(* Logix 5000 project; controller ANG1E_AOI_CompactLogix_RSLogix_V28 vendor 1 type 14 code 108 rev 28.11; software revision 28.00; part 2 of 5 *)
(* tags used below, declared in another part *)
   Least_Significant_Word : INT;

ADD_ON_INSTRUCTION AMCI_ANG1E_Hold   (* revision 1.1, vendor AMCI *)
// Revision note:
// Version 1.1 added the slot_axis number and the input parameters can now be tags or discrete values.
VAR_INPUT
   slot_axis_number : INT; {required}
END_VAR
VAR_IN_OUT
   AMCI_ANG1E_output_data : INT[10]; {required}
END_VAR
VAR
   command_data_block : INT[10];
        [5]   // Lower Programmed Speed
        [0]   // Command Bits MSW
        [1]   // Command Bits LSW
        [3]   // Lower Target Position
        [2]   // Upper Target Position
        [4]   // Upper Programmed Speed
   index : INT;
END_VAR

ROUTINE Logic   (* ladder *)
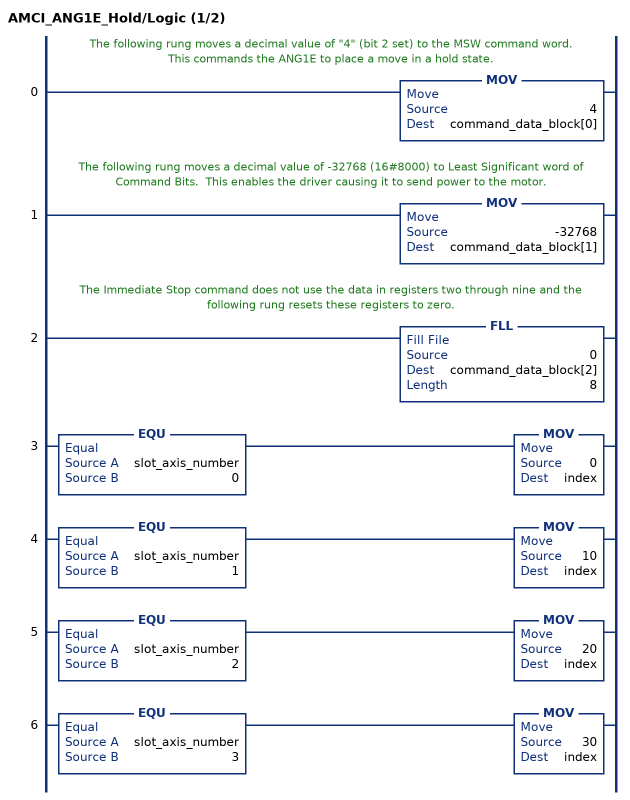
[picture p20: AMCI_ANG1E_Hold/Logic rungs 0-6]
   // The following rung moves a decimal value of "4" (bit 2 set) to the MSW command word.  This commands the ANG1E to place a move in a hold state.
   0: MOV(4,command_data_block[0]);
   // The following rung moves a decimal value of -32768 (16#8000) to Least Significant word of Command Bits.  This enables the driver causing it to send power to the motor.
   1: MOV(-32768,command_data_block[1]);
   // The Immediate Stop command does not use the data in registers two through nine and the following rung resets these registers to zero.
   2: FLL(0,command_data_block[2],8);
   3: EQU(slot_axis_number,0)MOV(0,index);
   4: EQU(slot_axis_number,1)MOV(10,index);
   5: EQU(slot_axis_number,2)MOV(20,index);
   6: EQU(slot_axis_number,3)MOV(30,index);
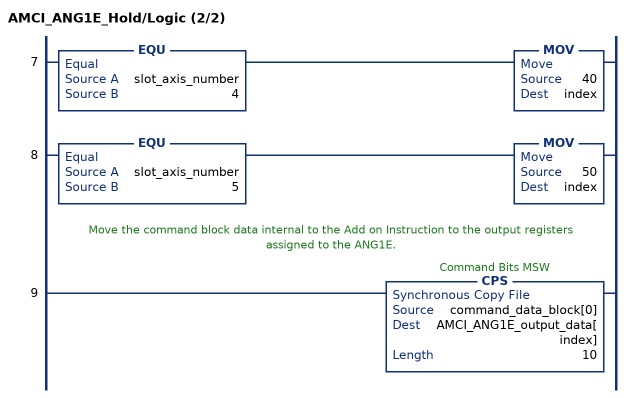
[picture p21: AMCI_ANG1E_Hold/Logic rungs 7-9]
   7: EQU(slot_axis_number,4)MOV(40,index);
   8: EQU(slot_axis_number,5)MOV(50,index);
   // Move the command block data internal to the Add on Instruction to the output registers assigned to the ANG1E.
   9: CPS(command_data_block[0],AMCI_ANG1E_output_data[index],10);
END_ROUTINE
END_ADD_ON_INSTRUCTION

ADD_ON_INSTRUCTION AMCI_ANG1E_Home_CCW   (* revision 5.0, vendor AMCI, ExecuteEnableInFalse *)
// Revision note:
// Version 5.0 added the (hidden) ability to program the motor current and unlatched the error bit if the rung goes false.
VAR_INPUT
   Axis_Status_Bits : INT; {required}
   slot_axis_number : INT; {required}
   Type_0_for_standard_1_for_indexed : BOOL;
   Programmed_Speed : DINT; {required}
   Acceleration : INT; {required}
   Deceleration : INT; {required}
   motor_current : INT;
   jerk : INT;
END_VAR
VAR_IN_OUT
   AMCI_ANG1E_output_data : INT[10]; {required}
END_VAR
VAR_OUTPUT
   EN : BOOL; {access Read Only, visible}
   ER : BOOL; {access Read Only, visible}
END_VAR
VAR
   Upper_Result_X_1000 : DINT;
   command_data_block : INT[10];
        [1]   // Command Bits LSW
        [3]   // Lower Target Position
        [5]   // Lower Programmed Speed
        [0]   // Command Bits MSW
        [2]   // Upper Target Position
        [4]   // Upper Programmed Speed
   index : INT;
END_VAR

ROUTINE EnableInFalse   (* ladder *)
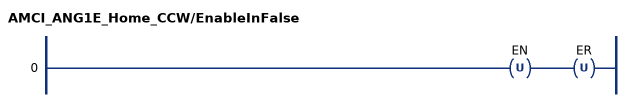
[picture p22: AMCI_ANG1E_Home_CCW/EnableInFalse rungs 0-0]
   0: OTU(EN)OTU(ER);
END_ROUTINE

ROUTINE Logic   (* ladder *)
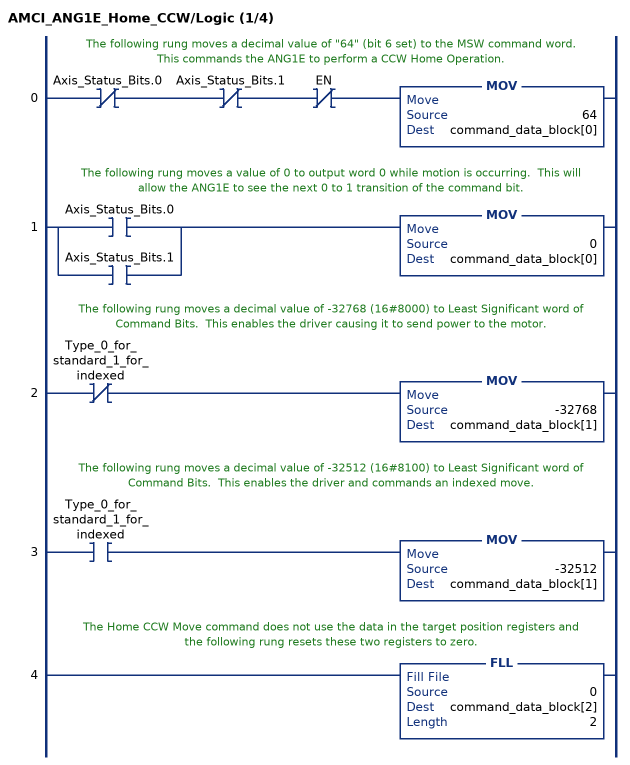
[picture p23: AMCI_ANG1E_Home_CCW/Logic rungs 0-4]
   // The following rung moves a decimal value of "64" (bit 6 set) to the MSW command word.  This commands the ANG1E to perform a CCW Home Operation.
   0: XIO(Axis_Status_Bits.0)XIO(Axis_Status_Bits.1)XIO(EN)MOV(64,command_data_block[0]);
   // The following rung moves a value of 0 to output word 0 while motion is occurring.  This will allow the ANG1E to see the next 0 to 1 transition of the command bit.
   1: [XIC(Axis_Status_Bits.0) ,XIC(Axis_Status_Bits.1) ]MOV(0,command_data_block[0]);
   // The following rung moves a decimal value of -32768 (16#8000) to Least Significant word of Command Bits.  This enables the driver causing it to send power to the motor.
   2: XIO(Type_0_for_standard_1_for_indexed)MOV(-32768,command_data_block[1]);
   // The following rung moves a decimal value of -32512 (16#8100) to Least Significant word of Command Bits.  This enables the driver and commands an indexed move.
   3: XIC(Type_0_for_standard_1_for_indexed)MOV(-32512,command_data_block[1]);
   // The Home CCW Move command does not use the data in the target position registers and the following rung resets these two registers to zero.
   4: FLL(0,command_data_block[2],2);
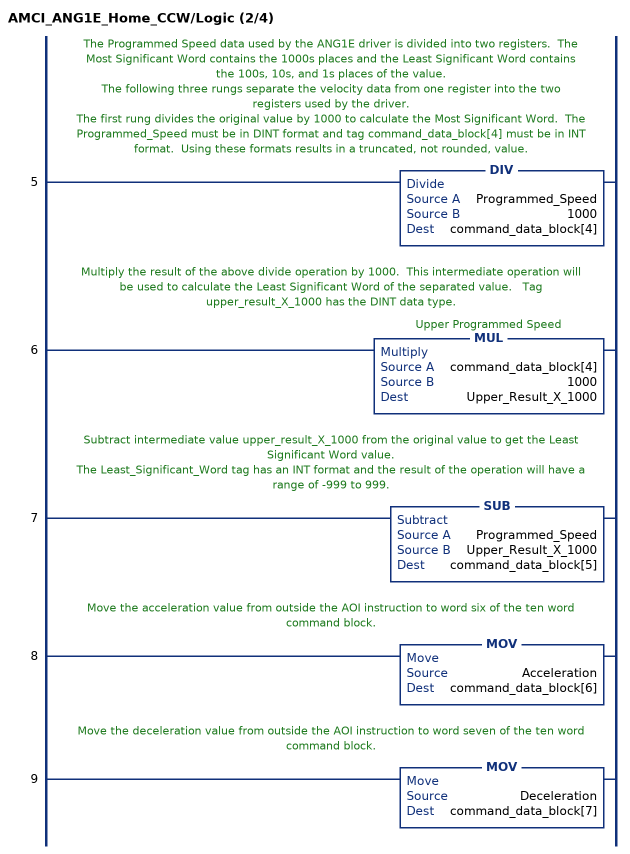
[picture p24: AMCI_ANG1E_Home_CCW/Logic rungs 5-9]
   // The Programmed Speed data used by the ANG1E driver is divided into two registers.  The Most Significant Word contains the 1000s places and the Least Significant Word contains the 100s, 10s, and 1s places of the value.
   // The following three rungs separate the velocity data from one register into the two registers used by the driver.
   // The first rung divides the original value by 1000 to calculate the Most Significant Word.  The Programmed_Speed must be in DINT format and tag command_data_block[4] must be in INT format.  Using these formats results in a truncated, not rounded, value.
   5: DIV(Programmed_Speed,1000,command_data_block[4]);
   // Multiply the result of the above divide operation by 1000.  This intermediate operation will be used to calculate the Least Significant Word of the separated value.   Tag upper_result_X_1000 has the DINT data type.
   6: MUL(command_data_block[4],1000,Upper_Result_X_1000);
   // Subtract intermediate value upper_result_X_1000 from the original value to get the Least Significant Word value.
   // The Least_Significant_Word tag has an INT format and the result of the operation will have a range of -999 to 999.
   7: SUB(Programmed_Speed,Upper_Result_X_1000,command_data_block[5]);
   // Move the acceleration value from outside the AOI instruction to word six of the ten word command block.
   8: MOV(Acceleration,command_data_block[6]);
   // Move the deceleration value from outside the AOI instruction to word seven of the ten word command block.
   9: MOV(Deceleration,command_data_block[7]);
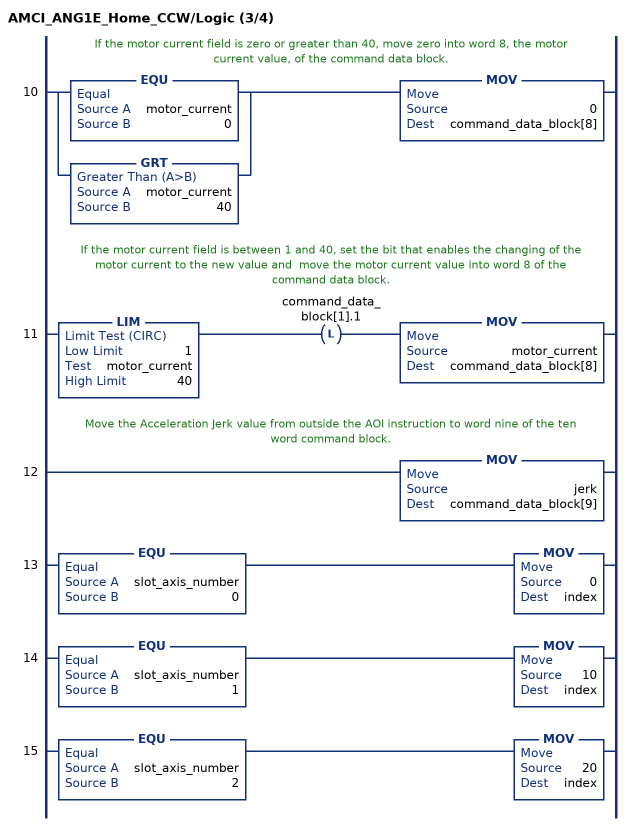
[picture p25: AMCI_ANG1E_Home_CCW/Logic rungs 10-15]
   // If the motor current field is zero or greater than 40, move zero into word 8, the motor current value, of the command data block.
   10: [EQU(motor_current,0) ,GRT(motor_current,40) ]MOV(0,command_data_block[8]);
   // If the motor current field is between 1 and 40, set the bit that enables the changing of the motor current to the new value and  move the motor current value into word 8 of the command data block.
   11: LIM(1,motor_current,40)OTL(command_data_block[1].1)MOV(motor_current,command_data_block[8]);
   // Move the Acceleration Jerk value from outside the AOI instruction to word nine of the ten word command block.
   12: MOV(jerk,command_data_block[9]);
   13: EQU(slot_axis_number,0)MOV(0,index);
   14: EQU(slot_axis_number,1)MOV(10,index);
   15: EQU(slot_axis_number,2)MOV(20,index);
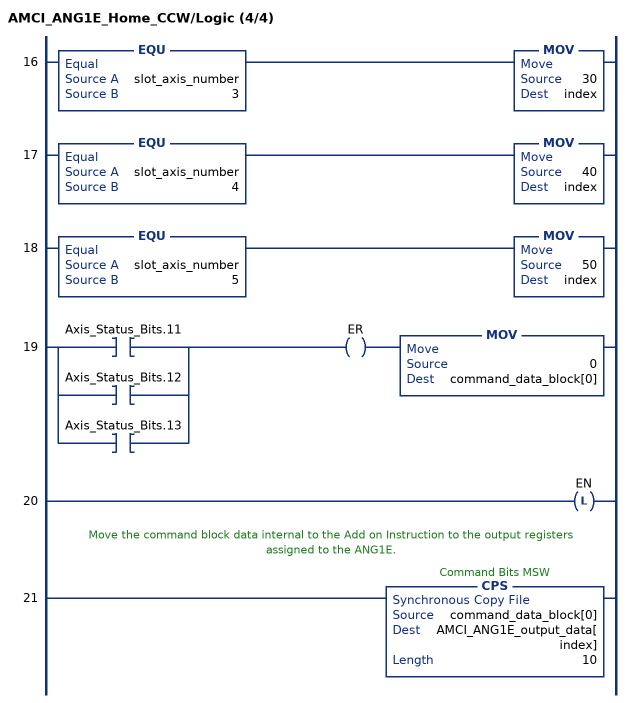
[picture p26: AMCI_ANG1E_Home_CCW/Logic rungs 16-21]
   16: EQU(slot_axis_number,3)MOV(30,index);
   17: EQU(slot_axis_number,4)MOV(40,index);
   18: EQU(slot_axis_number,5)MOV(50,index);
   19: [XIC(Axis_Status_Bits.11) ,XIC(Axis_Status_Bits.12) ,XIC(Axis_Status_Bits.13) ]OTE(ER)MOV(0,command_data_block[0]);
   20: OTL(EN);
   // Move the command block data internal to the Add on Instruction to the output registers assigned to the ANG1E.
   21: CPS(command_data_block[0],AMCI_ANG1E_output_data[index],10);
END_ROUTINE
END_ADD_ON_INSTRUCTION

ADD_ON_INSTRUCTION AMCI_ANG1E_Home_CW   (* revision 5.0, vendor AMCI, ExecuteEnableInFalse *)
// Revision note:
// Version 5.0 added the (hidden) ability to program the motor current and unlatched the error bit if the rung goes false.
VAR_INPUT
   Axis_Status_Bits : INT; {required}
   slot_axis_number : INT; {required}
   type_0_for_standard_1_for_indexed : BOOL;
   Programmed_Speed : DINT; {required}
   Acceleration : INT; {required}
   Deceleration : INT; {required}
   motor_current : INT;
   jerk : INT;
END_VAR
VAR_IN_OUT
   AMCI_ANG1E_output_data : INT[10]; {required}
END_VAR
VAR_OUTPUT
   EN : BOOL; {access Read Only, visible}
   ER : BOOL; {access Read Only, visible}
END_VAR
VAR
   Upper_Result_X_1000 : DINT;
   command_data_block : INT[10];
        [1]   // Command Bits LSW
        [3]   // Lower Target Position
        [5]   // Lower Programmed Speed
        [0]   // Command Bits MSW
        [2]   // Upper Target Position
        [4]   // Upper Programmed Speed
   index : INT;
END_VAR

ROUTINE EnableInFalse   (* ladder *)
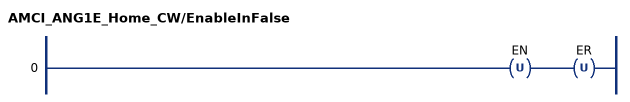
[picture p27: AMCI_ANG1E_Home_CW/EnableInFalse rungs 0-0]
   0: OTU(EN)OTU(ER);
END_ROUTINE

ROUTINE Logic   (* ladder *)
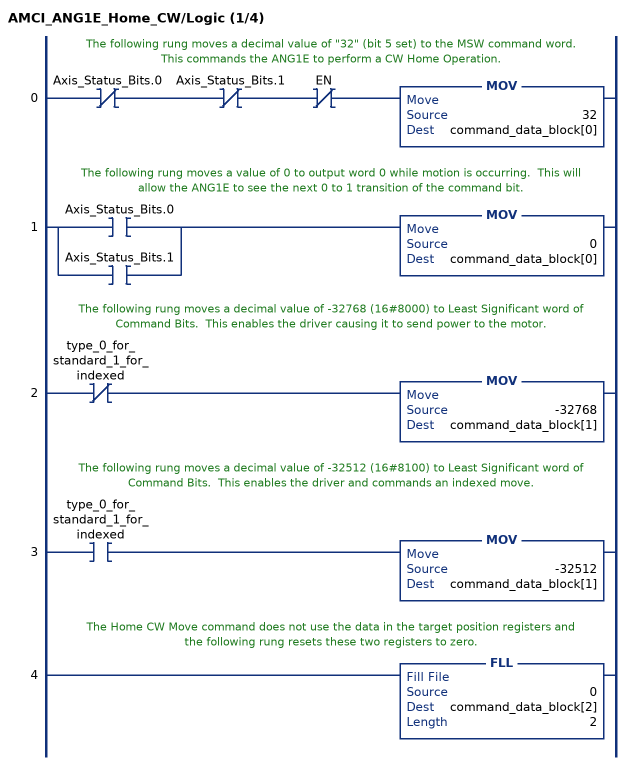
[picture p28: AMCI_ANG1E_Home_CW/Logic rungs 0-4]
   // The following rung moves a decimal value of "32" (bit 5 set) to the MSW command word.  This commands the ANG1E to perform a CW Home Operation.
   0: XIO(Axis_Status_Bits.0)XIO(Axis_Status_Bits.1)XIO(EN)MOV(32,command_data_block[0]);
   // The following rung moves a value of 0 to output word 0 while motion is occurring.  This will allow the ANG1E to see the next 0 to 1 transition of the command bit.
   1: [XIC(Axis_Status_Bits.0) ,XIC(Axis_Status_Bits.1) ]MOV(0,command_data_block[0]);
   // The following rung moves a decimal value of -32768 (16#8000) to Least Significant word of Command Bits.  This enables the driver causing it to send power to the motor.
   2: XIO(type_0_for_standard_1_for_indexed)MOV(-32768,command_data_block[1]);
   // The following rung moves a decimal value of -32512 (16#8100) to Least Significant word of Command Bits.  This enables the driver and commands an indexed move.
   3: XIC(type_0_for_standard_1_for_indexed)MOV(-32512,command_data_block[1]);
   // The Home CW Move command does not use the data in the target position registers and the following rung resets these two registers to zero.
   4: FLL(0,command_data_block[2],2);
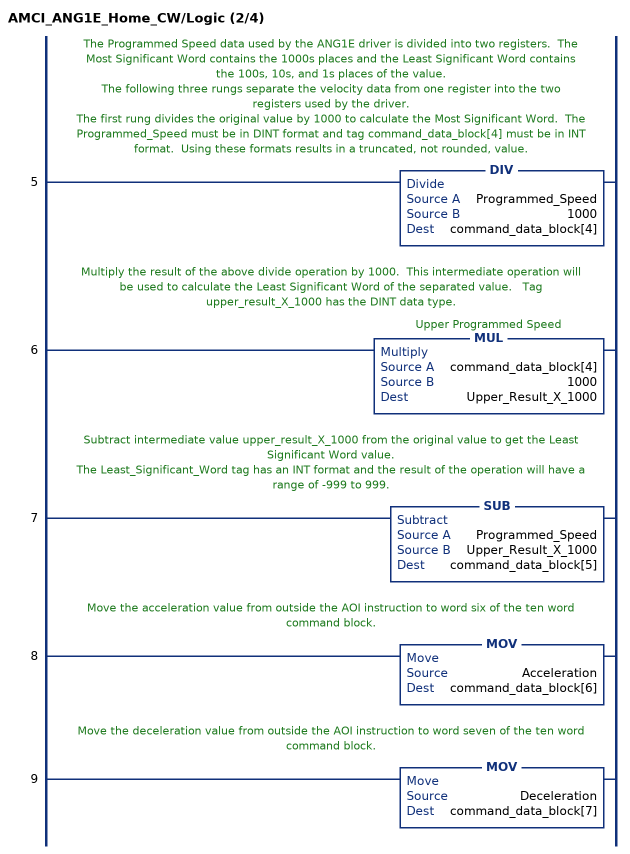
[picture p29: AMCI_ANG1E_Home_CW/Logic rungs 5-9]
   // The Programmed Speed data used by the ANG1E driver is divided into two registers.  The Most Significant Word contains the 1000s places and the Least Significant Word contains the 100s, 10s, and 1s places of the value.
   // The following three rungs separate the velocity data from one register into the two registers used by the driver.
   // The first rung divides the original value by 1000 to calculate the Most Significant Word.  The Programmed_Speed must be in DINT format and tag command_data_block[4] must be in INT format.  Using these formats results in a truncated, not rounded, value.
   5: DIV(Programmed_Speed,1000,command_data_block[4]);
   // Multiply the result of the above divide operation by 1000.  This intermediate operation will be used to calculate the Least Significant Word of the separated value.   Tag upper_result_X_1000 has the DINT data type.
   6: MUL(command_data_block[4],1000,Upper_Result_X_1000);
   // Subtract intermediate value upper_result_X_1000 from the original value to get the Least Significant Word value.
   // The Least_Significant_Word tag has an INT format and the result of the operation will have a range of -999 to 999.
   7: SUB(Programmed_Speed,Upper_Result_X_1000,command_data_block[5]);
   // Move the acceleration value from outside the AOI instruction to word six of the ten word command block.
   8: MOV(Acceleration,command_data_block[6]);
   // Move the deceleration value from outside the AOI instruction to word seven of the ten word command block.
   9: MOV(Deceleration,command_data_block[7]);
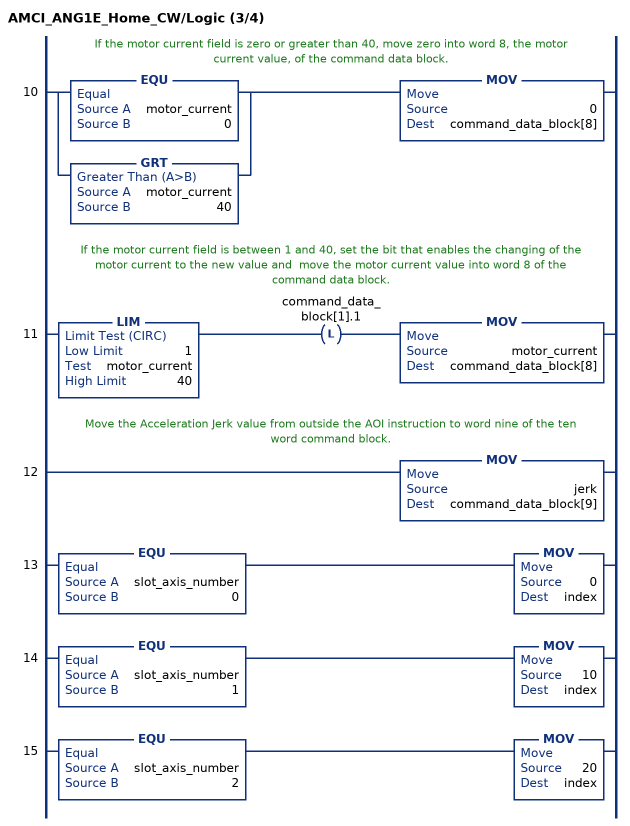
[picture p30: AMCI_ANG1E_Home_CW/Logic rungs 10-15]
   // If the motor current field is zero or greater than 40, move zero into word 8, the motor current value, of the command data block.
   10: [EQU(motor_current,0) ,GRT(motor_current,40) ]MOV(0,command_data_block[8]);
   // If the motor current field is between 1 and 40, set the bit that enables the changing of the motor current to the new value and  move the motor current value into word 8 of the command data block.
   11: LIM(1,motor_current,40)OTL(command_data_block[1].1)MOV(motor_current,command_data_block[8]);
   // Move the Acceleration Jerk value from outside the AOI instruction to word nine of the ten word command block.
   12: MOV(jerk,command_data_block[9]);
   13: EQU(slot_axis_number,0)MOV(0,index);
   14: EQU(slot_axis_number,1)MOV(10,index);
   15: EQU(slot_axis_number,2)MOV(20,index);
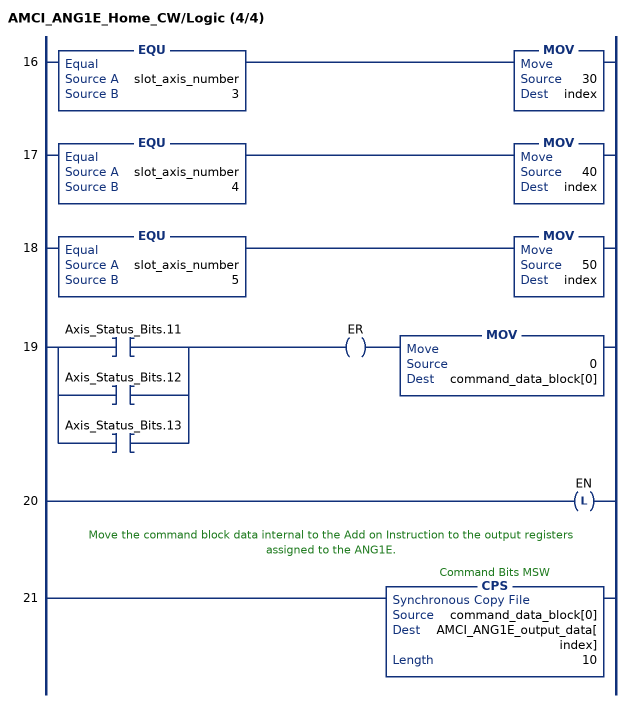
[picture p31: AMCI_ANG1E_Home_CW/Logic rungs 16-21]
   16: EQU(slot_axis_number,3)MOV(30,index);
   17: EQU(slot_axis_number,4)MOV(40,index);
   18: EQU(slot_axis_number,5)MOV(50,index);
   19: [XIC(Axis_Status_Bits.11) ,XIC(Axis_Status_Bits.12) ,XIC(Axis_Status_Bits.13) ]OTE(ER)MOV(0,command_data_block[0]);
   20: OTL(EN);
   // Move the command block data internal to the Add on Instruction to the output registers assigned to the ANG1E.
   21: CPS(command_data_block[0],AMCI_ANG1E_output_data[index],10);
END_ROUTINE
END_ADD_ON_INSTRUCTION

ADD_ON_INSTRUCTION AMCI_ANG1E_Immediate_Stop   (* revision 1.1, vendor AMCI *)
// Revision note:
// Version 1.1 added the slot_axis number and the input parameters can now be tags or discrete values.
VAR_INPUT
   slot_axis_number : INT; {required}
END_VAR
VAR_IN_OUT
   AMCI_ANG1E_output_data : INT[10]; {required}
END_VAR
VAR
   command_data_block : INT[10];
        [1]   // Command Bits LSW
        [3]   // Lower Target Position
        [5]   // Lower Programmed Speed
        [0]   // Command Bits MSW
        [2]   // Upper Target Position
        [4]   // Upper Programmed Speed
   index : INT;
END_VAR

ROUTINE Logic   (* ladder *)
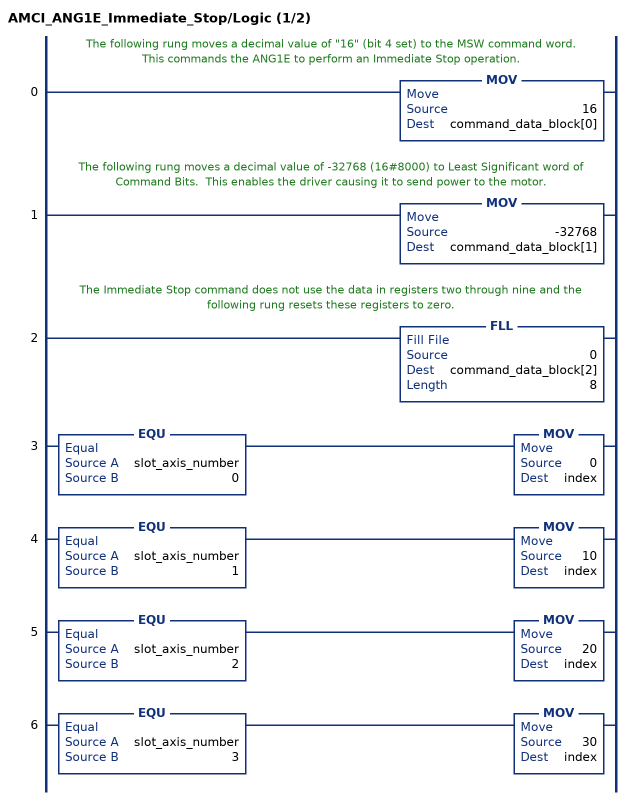
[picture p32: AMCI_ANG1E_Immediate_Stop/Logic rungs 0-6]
   // The following rung moves a decimal value of "16" (bit 4 set) to the MSW command word.  This commands the ANG1E to perform an Immediate Stop operation.
   0: MOV(16,command_data_block[0]);
   // The following rung moves a decimal value of -32768 (16#8000) to Least Significant word of Command Bits.  This enables the driver causing it to send power to the motor.
   1: MOV(-32768,command_data_block[1]);
   // The Immediate Stop command does not use the data in registers two through nine and the following rung resets these registers to zero.
   2: FLL(0,command_data_block[2],8);
   3: EQU(slot_axis_number,0)MOV(0,index);
   4: EQU(slot_axis_number,1)MOV(10,index);
   5: EQU(slot_axis_number,2)MOV(20,index);
   6: EQU(slot_axis_number,3)MOV(30,index);
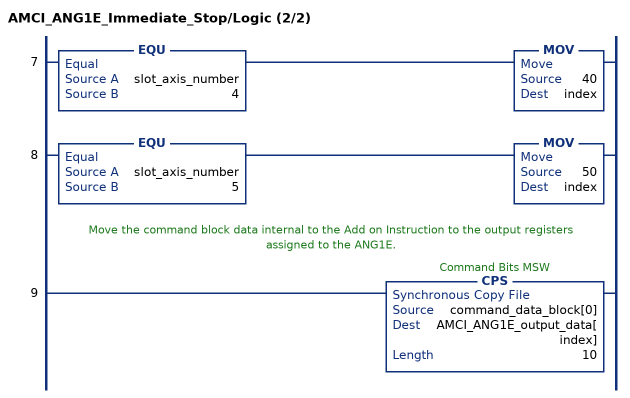
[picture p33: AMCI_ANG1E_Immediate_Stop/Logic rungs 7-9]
   7: EQU(slot_axis_number,4)MOV(40,index);
   8: EQU(slot_axis_number,5)MOV(50,index);
   // Move the command block data internal to the Add on Instruction to the output registers assigned to the ANG1E.
   9: CPS(command_data_block[0],AMCI_ANG1E_output_data[index],10);
END_ROUTINE
END_ADD_ON_INSTRUCTION

ADD_ON_INSTRUCTION AMCI_ANG1E_Jog_CCW   (* revision 5.0, vendor AMCI, ExecuteEnableInFalse *)
// Revision note:
// Version 5.0 added the (hidden) ability to program the motor current and unlatched the error bit if the rung goes false.
VAR_INPUT
   Axis_Status_Bits : DINT; {required}
   slot_axis_number : INT; {required}
   Programmed_Speed : DINT; {required}
   Acceleration : INT; {required}
   Deceleration : INT; {required}
   motor_current : INT;
   jerk : INT;
END_VAR
VAR_IN_OUT
   AMCI_ANG1E_output_data : INT[10]; {required}
END_VAR
VAR_OUTPUT
   EN : BOOL; {access Read Only, visible}
   Jog_CCW_Occurring : BOOL; {access Read Only, visible}
   ER : BOOL; {access Read Only, visible}
END_VAR
VAR
   Upper_Result_X_1000 : DINT;
   command_data_block : INT[10];
        [1]   // Command Bits LSW
        [3]   // Lower Target Position
        [5]   // Lower Programmed Speed
        [0]   // Command Bits MSW
        [2]   // Upper Target Position
        [4]   // Upper Programmed Speed
   index : INT;
END_VAR

ROUTINE EnableInFalse   (* ladder *)
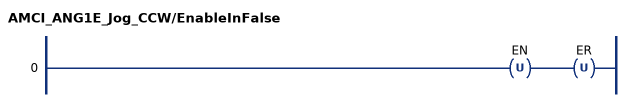
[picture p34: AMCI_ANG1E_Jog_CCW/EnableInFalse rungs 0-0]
   0: OTU(EN)OTU(ER);
END_ROUTINE

ROUTINE Logic   (* ladder *)
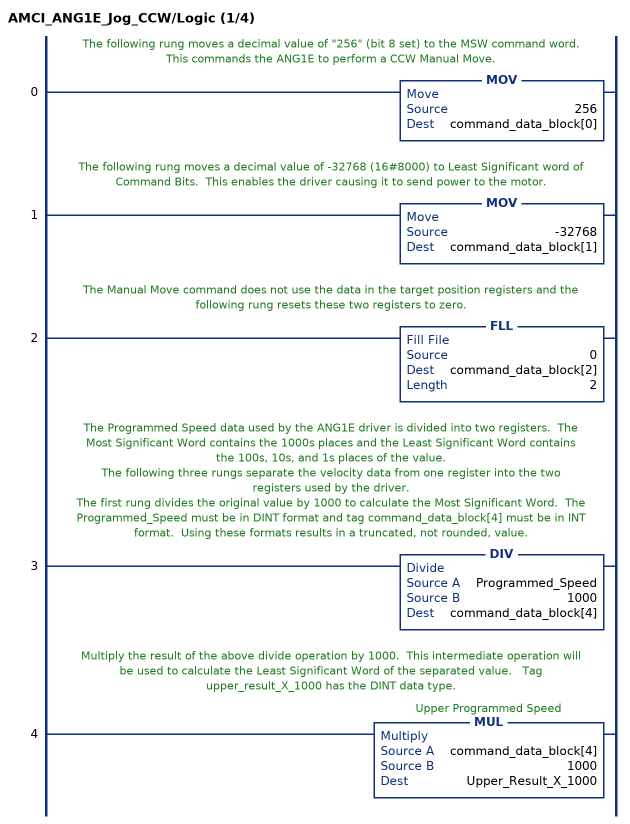
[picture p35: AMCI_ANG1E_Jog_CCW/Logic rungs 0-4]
   // The following rung moves a decimal value of "256" (bit 8 set) to the MSW command word.  This commands the ANG1E to perform a CCW Manual Move.
   0: MOV(256,command_data_block[0]);
   // The following rung moves a decimal value of -32768 (16#8000) to Least Significant word of Command Bits.  This enables the driver causing it to send power to the motor.
   1: MOV(-32768,command_data_block[1]);
   // The Manual Move command does not use the data in the target position registers and the following rung resets these two registers to zero.
   2: FLL(0,command_data_block[2],2);
   // The Programmed Speed data used by the ANG1E driver is divided into two registers.  The Most Significant Word contains the 1000s places and the Least Significant Word contains the 100s, 10s, and 1s places of the value.
   // The following three rungs separate the velocity data from one register into the two registers used by the driver.
   // The first rung divides the original value by 1000 to calculate the Most Significant Word.  The Programmed_Speed must be in DINT format and tag command_data_block[4] must be in INT format.  Using these formats results in a truncated, not rounded, value.
   3: DIV(Programmed_Speed,1000,command_data_block[4]);
   // Multiply the result of the above divide operation by 1000.  This intermediate operation will be used to calculate the Least Significant Word of the separated value.   Tag upper_result_X_1000 has the DINT data type.
   4: MUL(command_data_block[4],1000,Upper_Result_X_1000);
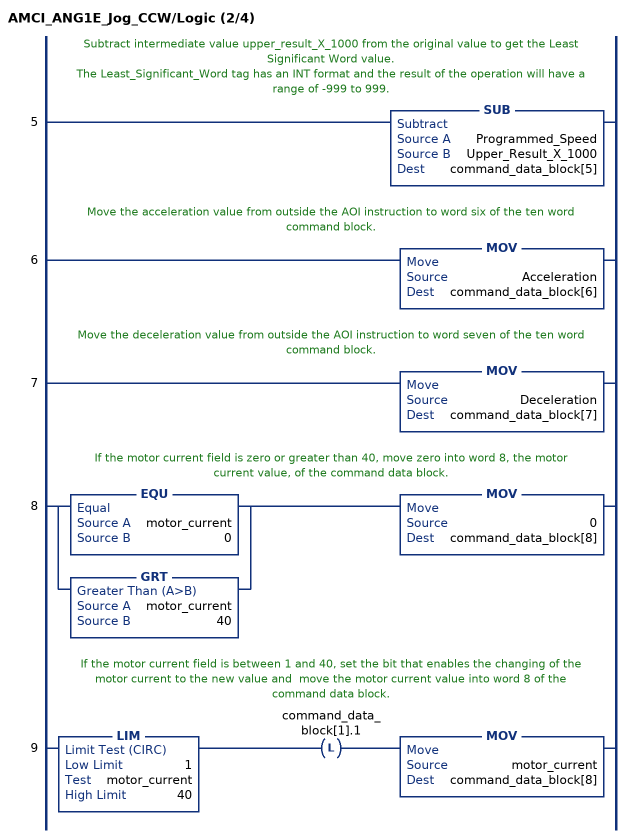
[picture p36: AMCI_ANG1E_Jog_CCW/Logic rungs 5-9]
   // Subtract intermediate value upper_result_X_1000 from the original value to get the Least Significant Word value.
   // The Least_Significant_Word tag has an INT format and the result of the operation will have a range of -999 to 999.
   5: SUB(Programmed_Speed,Upper_Result_X_1000,command_data_block[5]);
   // Move the acceleration value from outside the AOI instruction to word six of the ten word command block.
   6: MOV(Acceleration,command_data_block[6]);
   // Move the deceleration value from outside the AOI instruction to word seven of the ten word command block.
   7: MOV(Deceleration,command_data_block[7]);
   // If the motor current field is zero or greater than 40, move zero into word 8, the motor current value, of the command data block.
   8: [EQU(motor_current,0) ,GRT(motor_current,40) ]MOV(0,command_data_block[8]);
   // If the motor current field is between 1 and 40, set the bit that enables the changing of the motor current to the new value and  move the motor current value into word 8 of the command data block.
   9: LIM(1,motor_current,40)OTL(command_data_block[1].1)MOV(motor_current,command_data_block[8]);
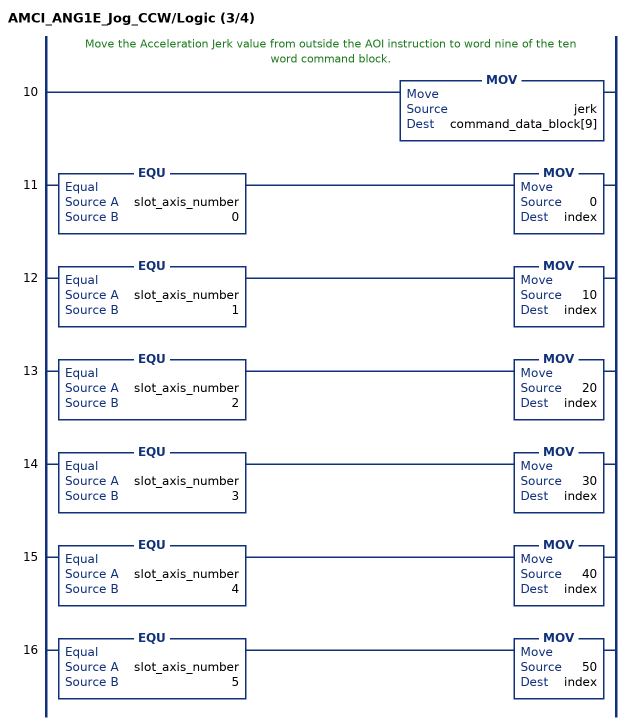
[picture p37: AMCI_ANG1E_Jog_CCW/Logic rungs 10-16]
   // Move the Acceleration Jerk value from outside the AOI instruction to word nine of the ten word command block.
   10: MOV(jerk,command_data_block[9]);
   11: EQU(slot_axis_number,0)MOV(0,index);
   12: EQU(slot_axis_number,1)MOV(10,index);
   13: EQU(slot_axis_number,2)MOV(20,index);
   14: EQU(slot_axis_number,3)MOV(30,index);
   15: EQU(slot_axis_number,4)MOV(40,index);
   16: EQU(slot_axis_number,5)MOV(50,index);
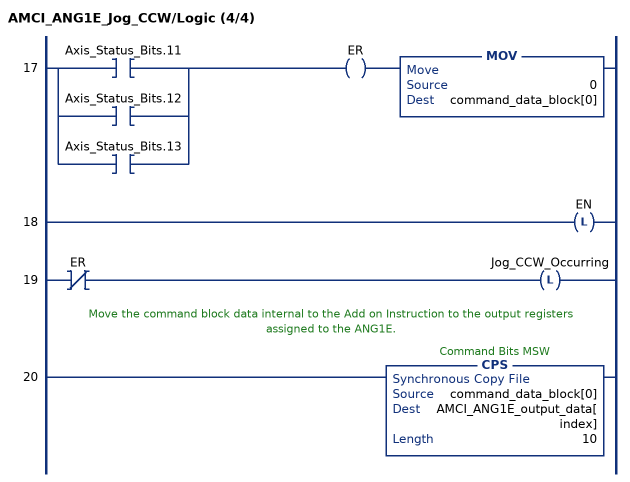
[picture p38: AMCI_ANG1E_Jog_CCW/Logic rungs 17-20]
   17: [XIC(Axis_Status_Bits.11) ,XIC(Axis_Status_Bits.12) ,XIC(Axis_Status_Bits.13) ]OTE(ER)MOV(0,command_data_block[0]);
   18: OTL(EN);
   19: XIO(ER)OTL(Jog_CCW_Occurring);
   // Move the command block data internal to the Add on Instruction to the output registers assigned to the ANG1E.
   20: CPS(command_data_block[0],AMCI_ANG1E_output_data[index],10);
END_ROUTINE
END_ADD_ON_INSTRUCTION
(* Logix 5000 project; controller ANG1E_AOI_CompactLogix_RSLogix_V28 vendor 1 type 14 code 108 rev 28.11; software revision 28.00; part 3 of 5 *)
(* tags used below, declared in another part *)
   Least_Significant_Word : INT;

ADD_ON_INSTRUCTION AMCI_ANG1E_Jog_CW   (* revision 5.0, vendor AMCI, ExecuteEnableInFalse *)
// Revision note:
// Version 5.0 added the (hidden) ability to program the motor current and unlatched the error bit if the rung goes false.
VAR_INPUT
   Axis_Status_Bits : INT; {required}
   Slot_Axis_Number : INT; {required}
   Programmed_Speed : DINT; {required}
   Acceleration : INT; {required}
   Deceleration : INT; {required}
   motor_current : INT;
   jerk : INT;
END_VAR
VAR_IN_OUT
   AMCI_ANG1E_output_data : INT[10]; {required}
END_VAR
VAR_OUTPUT
   EN : BOOL; {access Read Only, visible}
   Jog_CW_Occurring : BOOL; {access Read Only, visible}
   ER : BOOL; {access Read Only, visible}
END_VAR
VAR
   Upper_Result_X_1000 : DINT;
   command_data_block : INT[10];
        [1]   // Command Bits LSW
        [3]   // Lower Target Position
        [5]   // Lower Programmed Speed
        [0]   // Command Bits MSW
        [2]   // Upper Target Position
        [4]   // Upper Programmed Speed
   index : INT;
END_VAR

ROUTINE EnableInFalse   (* ladder *)
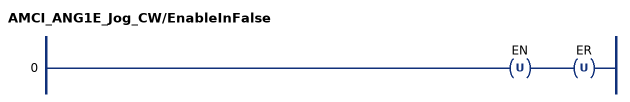
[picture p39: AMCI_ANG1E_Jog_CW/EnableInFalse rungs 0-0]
   0: OTU(EN)OTU(ER);
END_ROUTINE

ROUTINE Logic   (* ladder *)
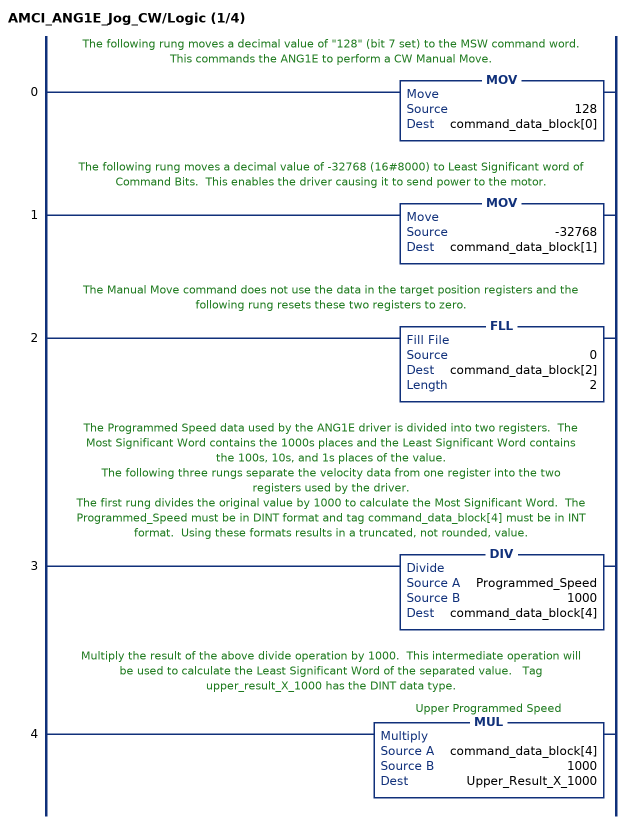
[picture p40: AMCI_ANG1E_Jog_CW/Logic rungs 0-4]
   // The following rung moves a decimal value of "128" (bit 7 set) to the MSW command word.  This commands the ANG1E to perform a CW Manual Move.
   0: MOV(128,command_data_block[0]);
   // The following rung moves a decimal value of -32768 (16#8000) to Least Significant word of Command Bits.  This enables the driver causing it to send power to the motor.
   1: MOV(-32768,command_data_block[1]);
   // The Manual Move command does not use the data in the target position registers and the following rung resets these two registers to zero.
   2: FLL(0,command_data_block[2],2);
   // The Programmed Speed data used by the ANG1E driver is divided into two registers.  The Most Significant Word contains the 1000s places and the Least Significant Word contains the 100s, 10s, and 1s places of the value.
   // The following three rungs separate the velocity data from one register into the two registers used by the driver.
   // The first rung divides the original value by 1000 to calculate the Most Significant Word.  The Programmed_Speed must be in DINT format and tag command_data_block[4] must be in INT format.  Using these formats results in a truncated, not rounded, value.
   3: DIV(Programmed_Speed,1000,command_data_block[4]);
   // Multiply the result of the above divide operation by 1000.  This intermediate operation will be used to calculate the Least Significant Word of the separated value.   Tag upper_result_X_1000 has the DINT data type.
   4: MUL(command_data_block[4],1000,Upper_Result_X_1000);
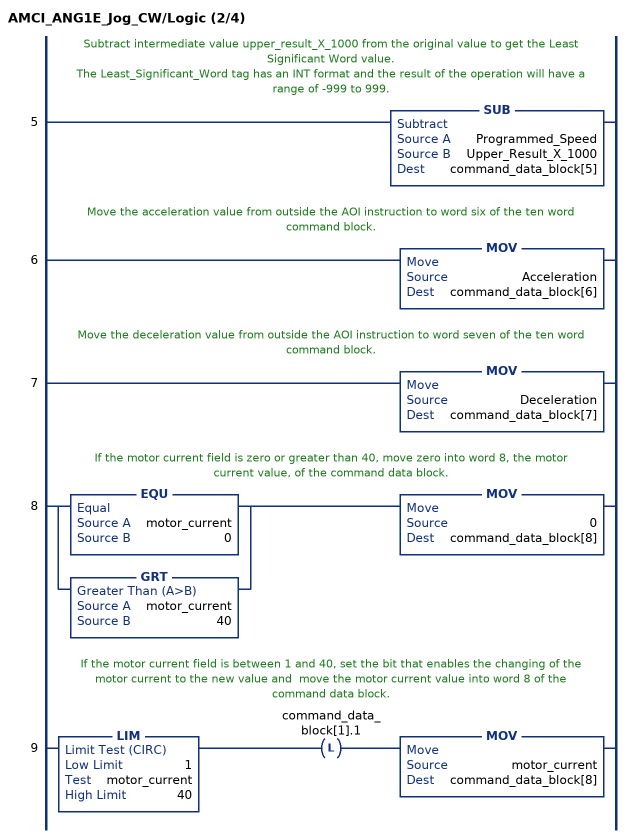
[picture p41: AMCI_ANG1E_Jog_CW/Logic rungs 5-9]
   // Subtract intermediate value upper_result_X_1000 from the original value to get the Least Significant Word value.
   // The Least_Significant_Word tag has an INT format and the result of the operation will have a range of -999 to 999.
   5: SUB(Programmed_Speed,Upper_Result_X_1000,command_data_block[5]);
   // Move the acceleration value from outside the AOI instruction to word six of the ten word command block.
   6: MOV(Acceleration,command_data_block[6]);
   // Move the deceleration value from outside the AOI instruction to word seven of the ten word command block.
   7: MOV(Deceleration,command_data_block[7]);
   // If the motor current field is zero or greater than 40, move zero into word 8, the motor current value, of the command data block.
   8: [EQU(motor_current,0) ,GRT(motor_current,40) ]MOV(0,command_data_block[8]);
   // If the motor current field is between 1 and 40, set the bit that enables the changing of the motor current to the new value and  move the motor current value into word 8 of the command data block.
   9: LIM(1,motor_current,40)OTL(command_data_block[1].1)MOV(motor_current,command_data_block[8]);
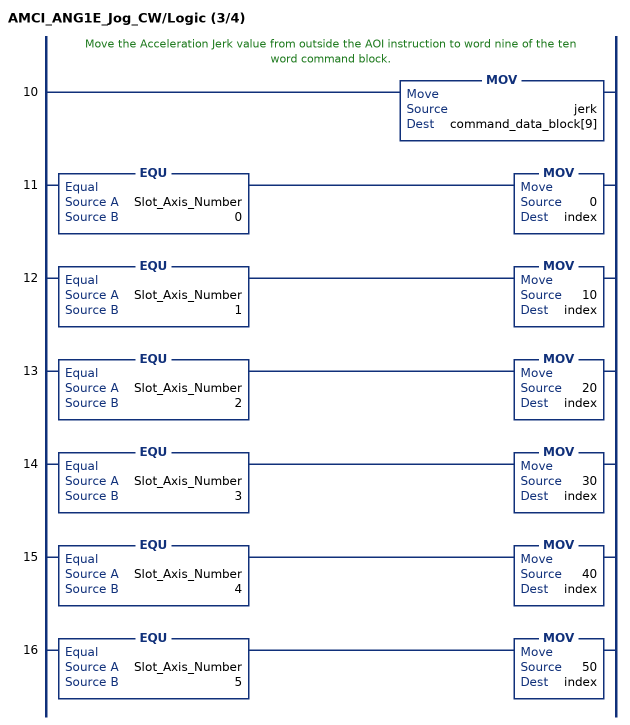
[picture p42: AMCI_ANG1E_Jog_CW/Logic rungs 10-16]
   // Move the Acceleration Jerk value from outside the AOI instruction to word nine of the ten word command block.
   10: MOV(jerk,command_data_block[9]);
   11: EQU(Slot_Axis_Number,0)MOV(0,index);
   12: EQU(Slot_Axis_Number,1)MOV(10,index);
   13: EQU(Slot_Axis_Number,2)MOV(20,index);
   14: EQU(Slot_Axis_Number,3)MOV(30,index);
   15: EQU(Slot_Axis_Number,4)MOV(40,index);
   16: EQU(Slot_Axis_Number,5)MOV(50,index);
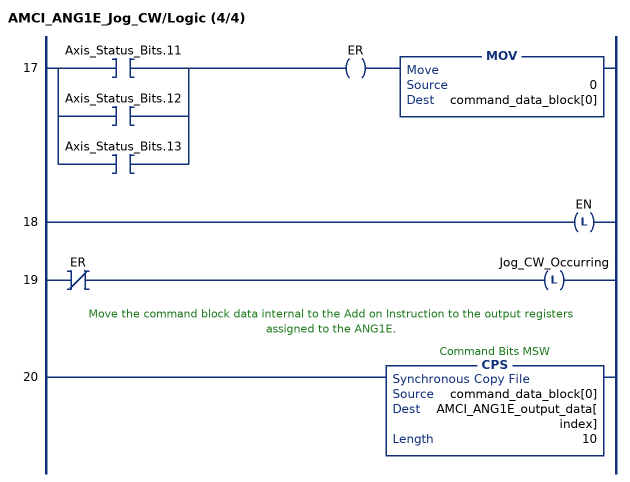
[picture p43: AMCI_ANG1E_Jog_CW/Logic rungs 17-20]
   17: [XIC(Axis_Status_Bits.11) ,XIC(Axis_Status_Bits.12) ,XIC(Axis_Status_Bits.13) ]OTE(ER)MOV(0,command_data_block[0]);
   18: OTL(EN);
   19: XIO(ER)OTL(Jog_CW_Occurring);
   // Move the command block data internal to the Add on Instruction to the output registers assigned to the ANG1E.
   20: CPS(command_data_block[0],AMCI_ANG1E_output_data[index],10);
END_ROUTINE
END_ADD_ON_INSTRUCTION

ADD_ON_INSTRUCTION AMCI_ANG1E_Preset_Encoder_Position   (* revision 1.1, vendor AMCI *)
// Revision note:
// Version 1.1 added the slot_axis number and the input parameters can now be tags or discrete values.
VAR_INPUT
   slot_axis_number : DINT; {required}
   Target_Position : DINT; {required}
END_VAR
VAR_IN_OUT
   AMCI_ANG1E_output_data : INT[10]; {required}
END_VAR
VAR
   Upper_Result_X_1000 : DINT;
   command_data_block : INT[10];
        [1]   // Command Bits LSW
        [3]   // Lower Target Position
        [5]   // Lower Programmed Speed
        [0]   // Command Bits MSW
        [2]   // Upper Target Position
        [4]   // Upper Programmed Speed
   index : INT;
END_VAR

ROUTINE Logic   (* ladder *)
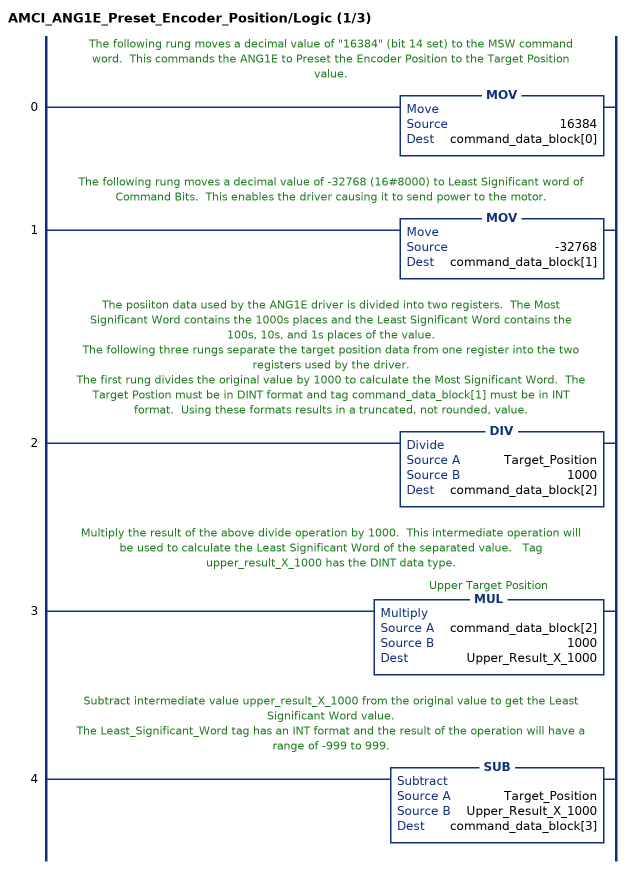
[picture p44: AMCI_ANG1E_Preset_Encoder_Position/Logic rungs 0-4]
   // The following rung moves a decimal value of "16384" (bit 14 set) to the MSW command word.  This commands the ANG1E to Preset the Encoder Position to the Target Position value.
   0: MOV(16384,command_data_block[0]);
   // The following rung moves a decimal value of -32768 (16#8000) to Least Significant word of Command Bits.  This enables the driver causing it to send power to the motor.
   1: MOV(-32768,command_data_block[1]);
   // The posiiton data used by the ANG1E driver is divided into two registers.  The Most Significant Word contains the 1000s places and the Least Significant Word contains the 100s, 10s, and 1s places of the value.
   // The following three rungs separate the target position data from one register into the two registers used by the driver.
   // The first rung divides the original value by 1000 to calculate the Most Significant Word.  The Target Postion must be in DINT format and tag command_data_block[1] must be in INT format.  Using these formats results in a truncated, not rounded, value.
   2: DIV(Target_Position,1000,command_data_block[2]);
   // Multiply the result of the above divide operation by 1000.  This intermediate operation will be used to calculate the Least Significant Word of the separated value.   Tag upper_result_X_1000 has the DINT data type.
   3: MUL(command_data_block[2],1000,Upper_Result_X_1000);
   // Subtract intermediate value upper_result_X_1000 from the original value to get the Least Significant Word value.
   // The Least_Significant_Word tag has an INT format and the result of the operation will have a range of -999 to 999.
   4: SUB(Target_Position,Upper_Result_X_1000,command_data_block[3]);
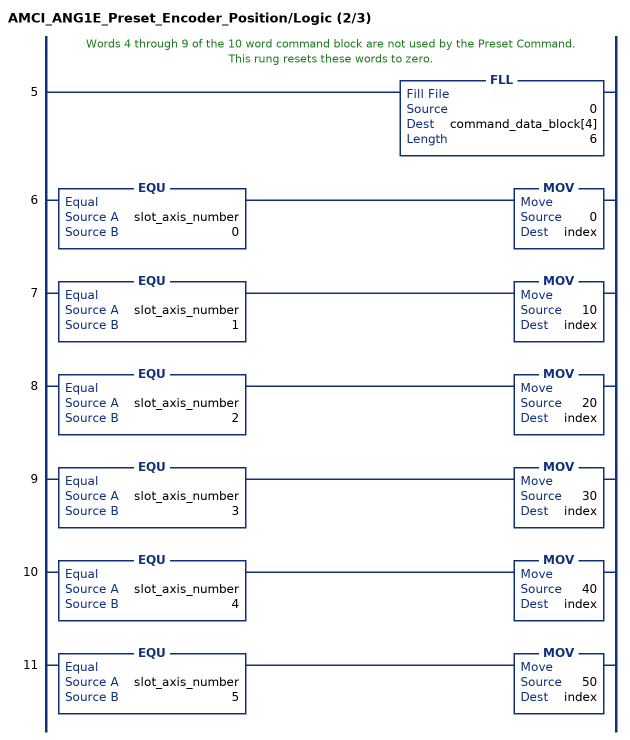
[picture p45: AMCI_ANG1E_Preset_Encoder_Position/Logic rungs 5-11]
   // Words 4 through 9 of the 10 word command block are not used by the Preset Command.  This rung resets these words to zero.
   5: FLL(0,command_data_block[4],6);
   6: EQU(slot_axis_number,0)MOV(0,index);
   7: EQU(slot_axis_number,1)MOV(10,index);
   8: EQU(slot_axis_number,2)MOV(20,index);
   9: EQU(slot_axis_number,3)MOV(30,index);
   10: EQU(slot_axis_number,4)MOV(40,index);
   11: EQU(slot_axis_number,5)MOV(50,index);
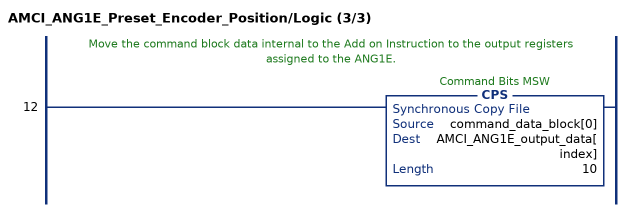
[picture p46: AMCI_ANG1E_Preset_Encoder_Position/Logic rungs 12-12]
   // Move the command block data internal to the Add on Instruction to the output registers assigned to the ANG1E.
   12: CPS(command_data_block[0],AMCI_ANG1E_output_data[index],10);
END_ROUTINE
END_ADD_ON_INSTRUCTION

ADD_ON_INSTRUCTION AMCI_ANG1E_Preset_Position   (* revision 1.1, vendor AMCI *)
// Revision note:
// Version 1.1 added the slot_axis number and the input parameters can now be tags or discrete values.
VAR_INPUT
   slot_axis_number : DINT; {required}
   Target_Position : DINT; {required}
END_VAR
VAR_IN_OUT
   AMCI_ANG1E_output_data : INT[10]; {required}
END_VAR
VAR
   Upper_Result_X_1000 : DINT;
   command_data_block : INT[10];
        [1]   // Command Bits LSW
        [3]   // Lower Target Position
        [5]   // Lower Programmed Speed
        [2]   // Upper Target Position
        [4]   // Upper Programmed Speed
        [0]   // Command Bits MSW
   index : INT;
END_VAR

ROUTINE Logic   (* ladder *)
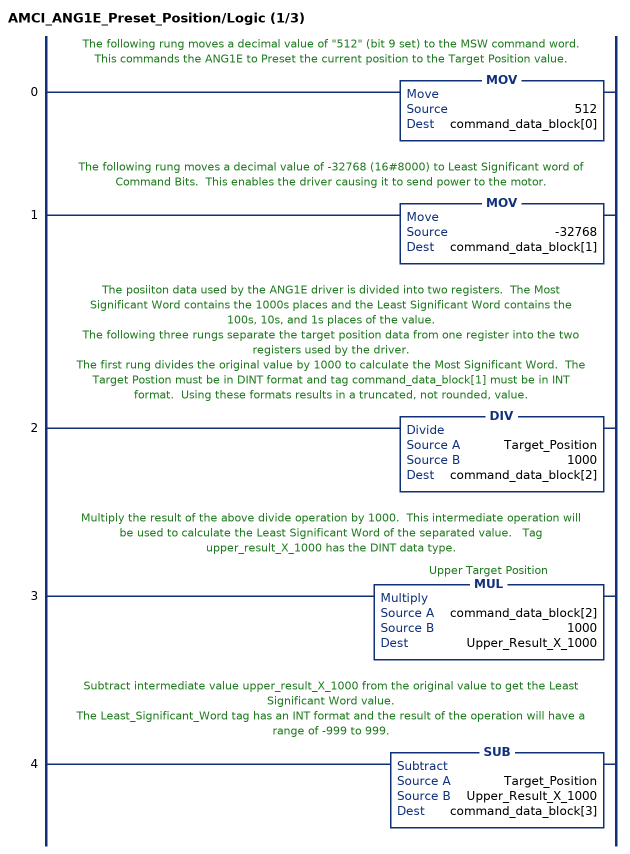
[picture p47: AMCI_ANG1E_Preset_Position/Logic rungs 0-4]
   // The following rung moves a decimal value of "512" (bit 9 set) to the MSW command word.  This commands the ANG1E to Preset the current position to the Target Position value.
   0: MOV(512,command_data_block[0]);
   // The following rung moves a decimal value of -32768 (16#8000) to Least Significant word of Command Bits.  This enables the driver causing it to send power to the motor.
   1: MOV(-32768,command_data_block[1]);
   // The posiiton data used by the ANG1E driver is divided into two registers.  The Most Significant Word contains the 1000s places and the Least Significant Word contains the 100s, 10s, and 1s places of the value.
   // The following three rungs separate the target position data from one register into the two registers used by the driver.
   // The first rung divides the original value by 1000 to calculate the Most Significant Word.  The Target Postion must be in DINT format and tag command_data_block[1] must be in INT format.  Using these formats results in a truncated, not rounded, value.
   2: DIV(Target_Position,1000,command_data_block[2]);
   // Multiply the result of the above divide operation by 1000.  This intermediate operation will be used to calculate the Least Significant Word of the separated value.   Tag upper_result_X_1000 has the DINT data type.
   3: MUL(command_data_block[2],1000,Upper_Result_X_1000);
   // Subtract intermediate value upper_result_X_1000 from the original value to get the Least Significant Word value.
   // The Least_Significant_Word tag has an INT format and the result of the operation will have a range of -999 to 999.
   4: SUB(Target_Position,Upper_Result_X_1000,command_data_block[3]);
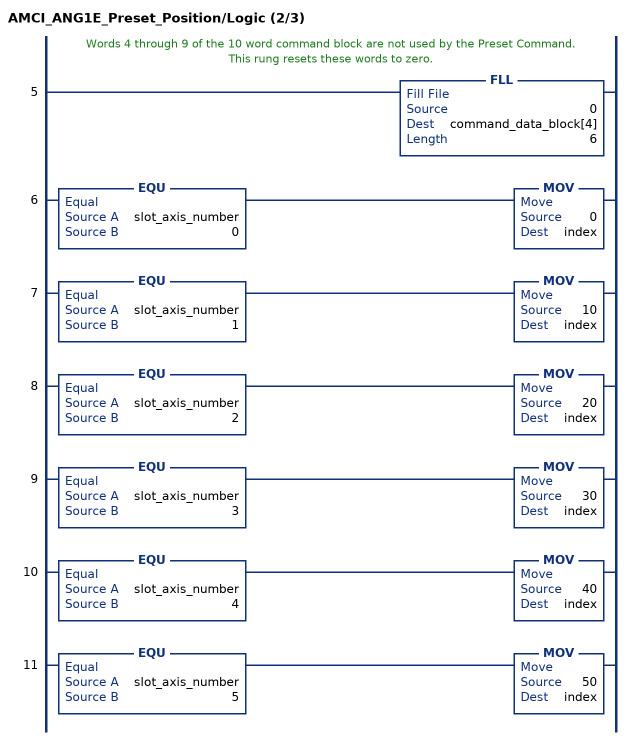
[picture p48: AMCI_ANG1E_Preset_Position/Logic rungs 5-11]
   // Words 4 through 9 of the 10 word command block are not used by the Preset Command.  This rung resets these words to zero.
   5: FLL(0,command_data_block[4],6);
   6: EQU(slot_axis_number,0)MOV(0,index);
   7: EQU(slot_axis_number,1)MOV(10,index);
   8: EQU(slot_axis_number,2)MOV(20,index);
   9: EQU(slot_axis_number,3)MOV(30,index);
   10: EQU(slot_axis_number,4)MOV(40,index);
   11: EQU(slot_axis_number,5)MOV(50,index);
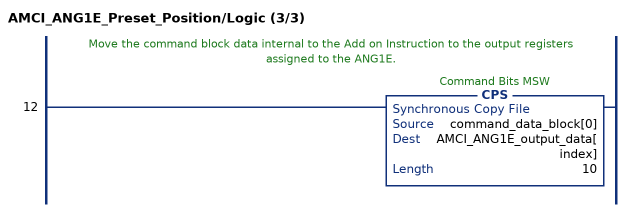
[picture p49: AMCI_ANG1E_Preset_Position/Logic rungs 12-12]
   // Move the command block data internal to the Add on Instruction to the output registers assigned to the ANG1E.
   12: CPS(command_data_block[0],AMCI_ANG1E_output_data[index],10);
END_ROUTINE
END_ADD_ON_INSTRUCTION

ADD_ON_INSTRUCTION AMCI_ANG1E_Program_Assembled_Move   (* revision 1.0 *)
VAR_INPUT
   Axis_Status_Bits : INT; {required}
   slot_axis_number : INT; {required}
   Number_of_Segments : DINT; {required}
   Segment_1_Distance : DINT; {required}
   Segment_1_Programmed_Speed : DINT; {required}
   Segment_1_Acceleration : INT; {required}
   Segment_1_Deceleration : INT; {required}
   Segment_2_Distance : DINT; {required}
   Segment_2_Programmed_Speed : DINT; {required}
   Segment_2_Acceleration : INT; {required}
   Segment_2_Deceleration : INT; {required}
   Segment_3_Distance : DINT; {required}
   Segment_3_Programmed_Speed : DINT; {required}
   Segment_3_Acceleration : INT; {required}
   Segment_3_Deceleration : INT; {required}
   Segment_4_Distance : DINT; {required}
   Segment_4_Programmed_Speed : DINT; {required}
   Segment_4_Acceleration : INT; {required}
   Segment_4_Deceleration : INT; {required}
   Segment_5_Distance : DINT; {required}
   Segment_5_Programmed_Speed : DINT; {required}
   Segment_5_Acceleration : INT; {required}
   Segment_5_Deceleration : INT; {required}
   Segment_6_Distance : DINT; {required}
   Segment_6_Programmed_Speed : DINT; {required}
   Segment_6_Acceleration : INT; {required}
   Segment_6_Deceleration : INT; {required}
   Segment_7_Distance : DINT; {required}
   Segment_7_Programmed_Speed : DINT; {required}
   Segment_7_Acceleration : INT; {required}
   Segment_7_Deceleration : INT; {required}
   Segment_8_Distance : DINT; {required}
   Segment_8_Programmed_Speed : DINT; {required}
   Segment_8_Acceleration : INT; {required}
   Segment_8_Deceleration : INT; {required}
   Segment_9_Distance : DINT; {required}
   Segment_9_Programmed_Speed : DINT; {required}
   Segment_9_Acceleration : INT; {required}
   Segment_9_Deceleration : INT; {required}
   Segment_10_Distance : DINT; {required}
   Segment_10_Programmed_Speed : DINT; {required}
   Segment_10_Acceleration : INT; {required}
   Segment_10_Deceleration : INT; {required}
   Segment_11_Distance : DINT; {required}
   Segment_11_Programmed_Speed : DINT; {required}
   Segment_11_Acceleration : INT; {required}
   Segment_11_Deceleration : INT; {required}
   Segment_12_Distance : DINT; {required}
   Segment_12_Programmed_Speed : DINT; {required}
   Segment_12_Acceleration : INT; {required}
   Segment_12_Deceleration : INT; {required}
   Segment_13_Distance : DINT; {required}
   Segment_13_Programmed_Speed : DINT; {required}
   Segment_13_Acceleration : INT; {required}
   Segment_13_Deceleration : INT; {required}
   Segment_14_Distance : DINT; {required}
   Segment_14_Programmed_Speed : DINT; {required}
   Segment_14_Acceleration : INT; {required}
   Segment_14_Deceleration : INT; {required}
   Segment_15_Distance : DINT; {required}
   Segment_15_Programmed_Speed : DINT; {required}
   Segment_15_Acceleration : INT; {required}
   Segment_15_Deceleration : INT; {required}
   Segment_16_Distance : DINT; {required}
   Segment_16_Programmed_Speed : DINT; {required}
   Segment_16_Acceleration : INT; {required}
   Segment_16_Deceleration : INT; {required}
END_VAR
VAR_IN_OUT
   AMCI_ANG1E_output_data : INT[10]; {required}
END_VAR
VAR_OUTPUT
   Assembled_Move_Programmed : BOOL; {access Read Only, visible}
END_VAR
VAR
   command_data_block : INT[10];
   Assembled_Move_setup : INT[10] := ([0] := 2048, [1] := -32768);
   Assembled_Move_counter : COUNTER;
   Programmed_Speed : DINT;
   Distance : DINT;
   upper_result_X_1000 : DINT;
   index : DINT;
END_VAR

ROUTINE Logic   (* ladder *)
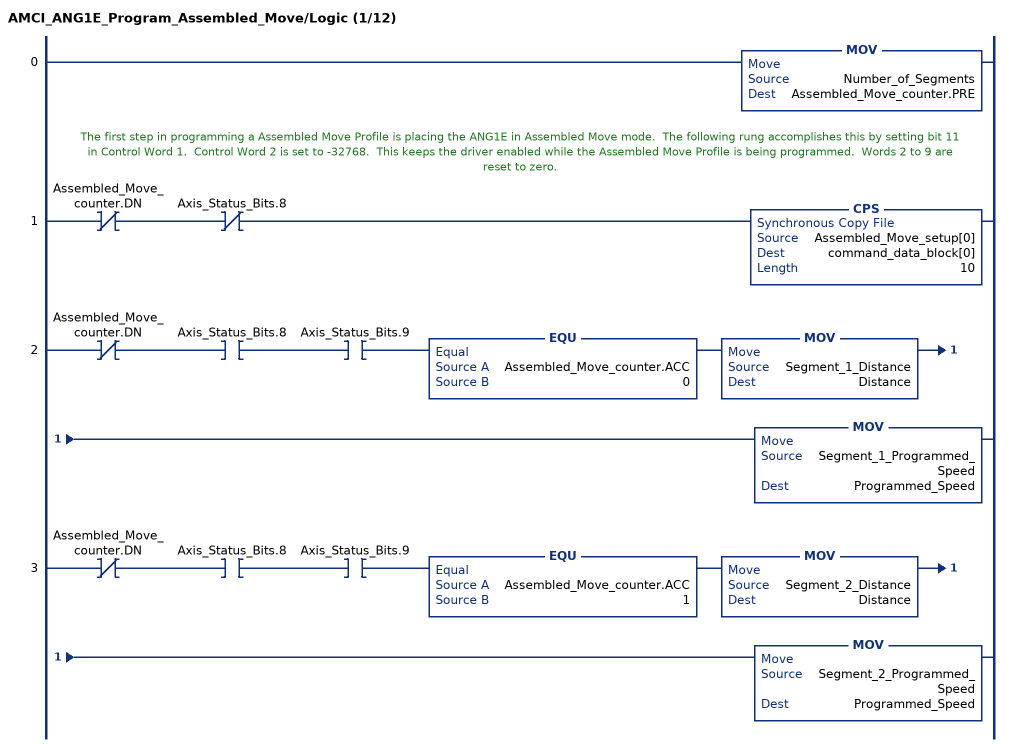
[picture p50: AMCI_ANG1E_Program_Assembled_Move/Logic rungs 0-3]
   0: MOV(Number_of_Segments,Assembled_Move_counter.PRE);
   // The first step in programming a Assembled Move Profile is placing the ANG1E in Assembled Move mode.  The following rung accomplishes this by setting bit 11 in Control Word 1.  Control Word 2 is set to -32768.  This keeps the driver enabled while the Assembled Move Profile is being programmed.  Words 2 to 9 are reset to zero.
   1: XIO(Assembled_Move_counter.DN)XIO(Axis_Status_Bits.8)CPS(Assembled_Move_setup[0],command_data_block[0],10);
   2: XIO(Assembled_Move_counter.DN)XIC(Axis_Status_Bits.8)XIC(Axis_Status_Bits.9)EQU(Assembled_Move_counter.ACC,0)MOV(Segment_1_Distance,Distance)MOV(Segment_1_Programmed_Speed,Programmed_Speed);
   3: XIO(Assembled_Move_counter.DN)XIC(Axis_Status_Bits.8)XIC(Axis_Status_Bits.9)EQU(Assembled_Move_counter.ACC,1)MOV(Segment_2_Distance,Distance)MOV(Segment_2_Programmed_Speed,Programmed_Speed);
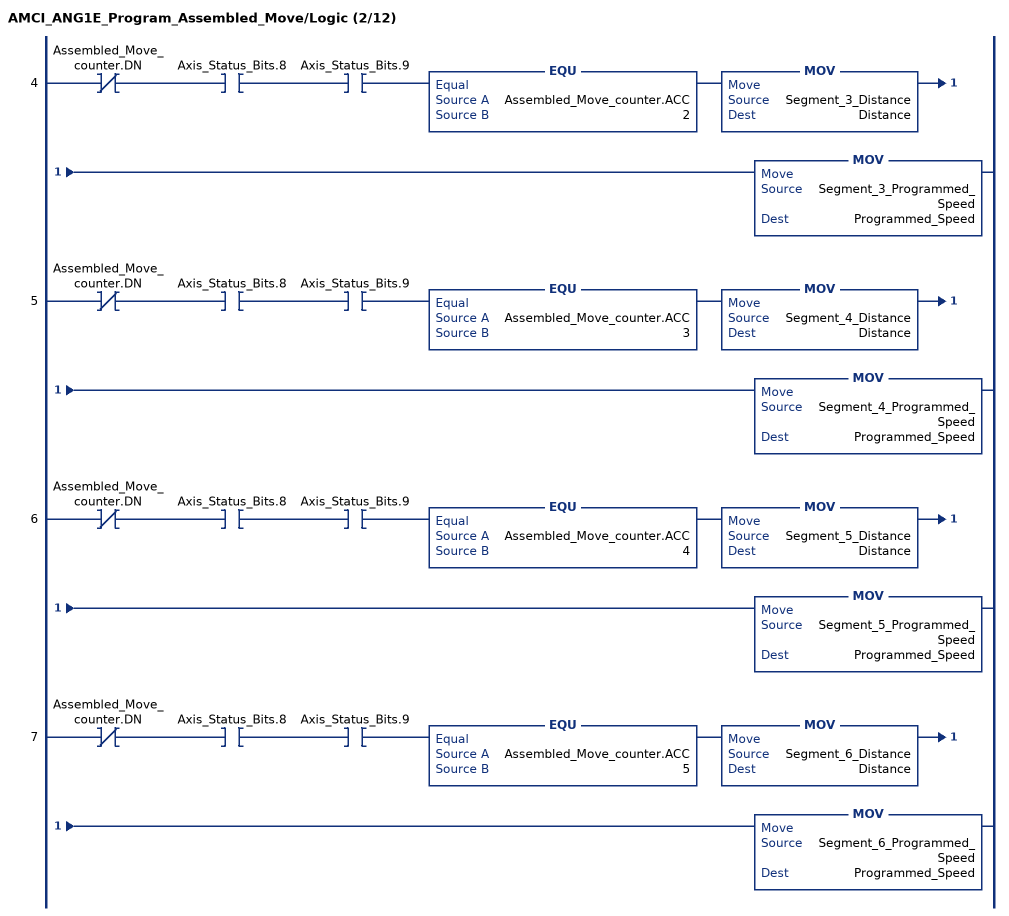
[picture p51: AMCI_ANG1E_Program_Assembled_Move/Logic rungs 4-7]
   4: XIO(Assembled_Move_counter.DN)XIC(Axis_Status_Bits.8)XIC(Axis_Status_Bits.9)EQU(Assembled_Move_counter.ACC,2)MOV(Segment_3_Distance,Distance)MOV(Segment_3_Programmed_Speed,Programmed_Speed);
   5: XIO(Assembled_Move_counter.DN)XIC(Axis_Status_Bits.8)XIC(Axis_Status_Bits.9)EQU(Assembled_Move_counter.ACC,3)MOV(Segment_4_Distance,Distance)MOV(Segment_4_Programmed_Speed,Programmed_Speed);
   6: XIO(Assembled_Move_counter.DN)XIC(Axis_Status_Bits.8)XIC(Axis_Status_Bits.9)EQU(Assembled_Move_counter.ACC,4)MOV(Segment_5_Distance,Distance)MOV(Segment_5_Programmed_Speed,Programmed_Speed);
   7: XIO(Assembled_Move_counter.DN)XIC(Axis_Status_Bits.8)XIC(Axis_Status_Bits.9)EQU(Assembled_Move_counter.ACC,5)MOV(Segment_6_Distance,Distance)MOV(Segment_6_Programmed_Speed,Programmed_Speed);
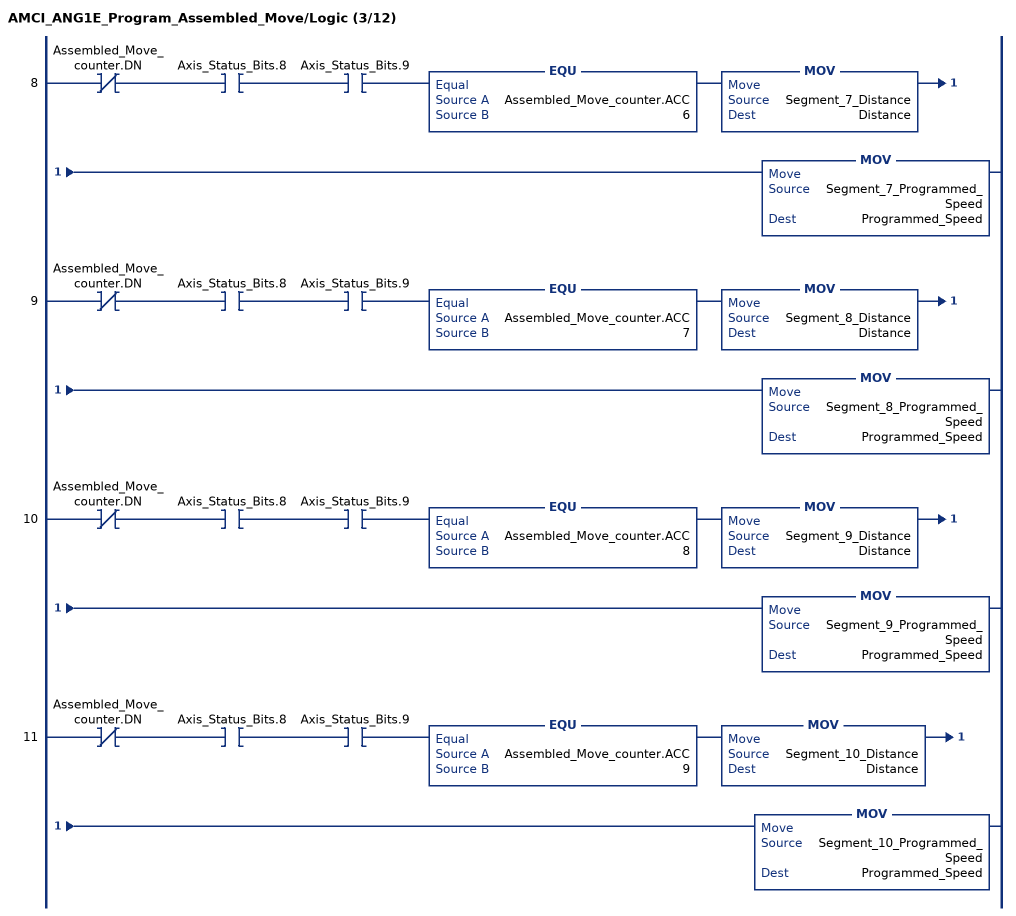
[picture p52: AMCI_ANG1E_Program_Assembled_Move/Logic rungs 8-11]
   8: XIO(Assembled_Move_counter.DN)XIC(Axis_Status_Bits.8)XIC(Axis_Status_Bits.9)EQU(Assembled_Move_counter.ACC,6)MOV(Segment_7_Distance,Distance)MOV(Segment_7_Programmed_Speed,Programmed_Speed);
   9: XIO(Assembled_Move_counter.DN)XIC(Axis_Status_Bits.8)XIC(Axis_Status_Bits.9)EQU(Assembled_Move_counter.ACC,7)MOV(Segment_8_Distance,Distance)MOV(Segment_8_Programmed_Speed,Programmed_Speed);
   10: XIO(Assembled_Move_counter.DN)XIC(Axis_Status_Bits.8)XIC(Axis_Status_Bits.9)EQU(Assembled_Move_counter.ACC,8)MOV(Segment_9_Distance,Distance)MOV(Segment_9_Programmed_Speed,Programmed_Speed);
   11: XIO(Assembled_Move_counter.DN)XIC(Axis_Status_Bits.8)XIC(Axis_Status_Bits.9)EQU(Assembled_Move_counter.ACC,9)MOV(Segment_10_Distance,Distance)MOV(Segment_10_Programmed_Speed,Programmed_Speed);
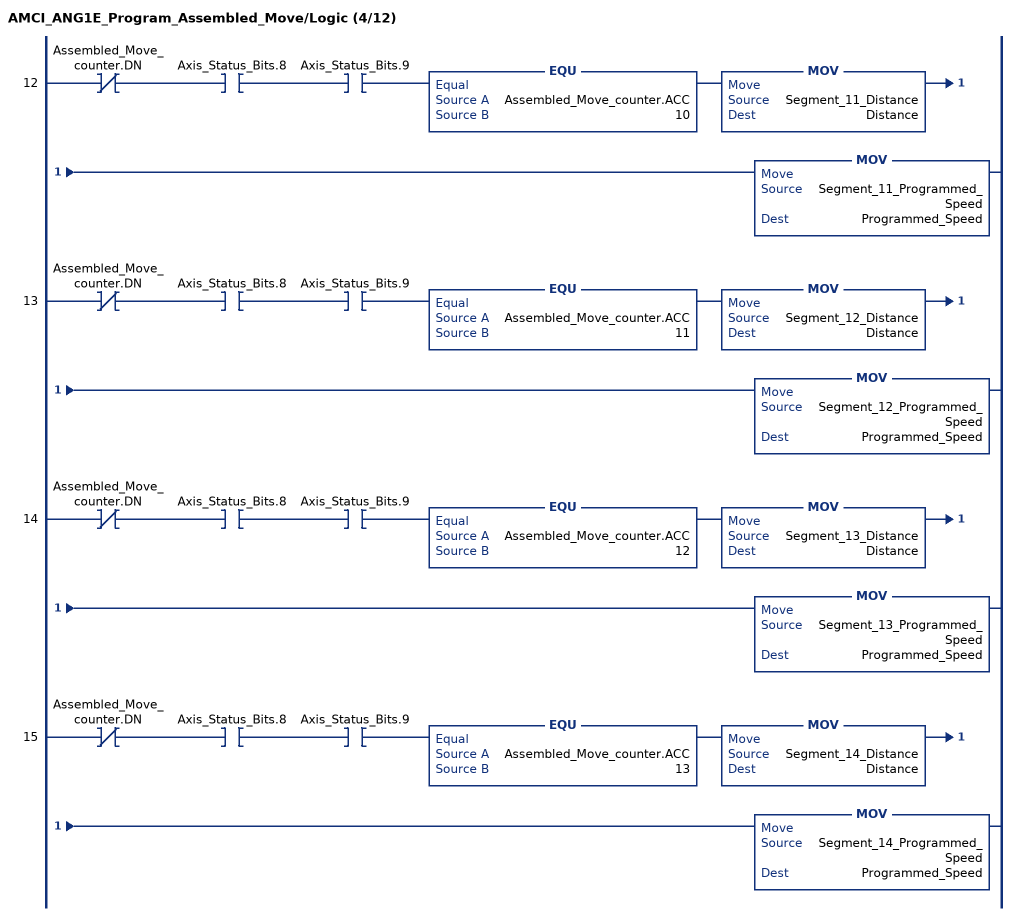
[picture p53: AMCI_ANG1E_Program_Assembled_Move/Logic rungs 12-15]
   12: XIO(Assembled_Move_counter.DN)XIC(Axis_Status_Bits.8)XIC(Axis_Status_Bits.9)EQU(Assembled_Move_counter.ACC,10)MOV(Segment_11_Distance,Distance)MOV(Segment_11_Programmed_Speed,Programmed_Speed);
   13: XIO(Assembled_Move_counter.DN)XIC(Axis_Status_Bits.8)XIC(Axis_Status_Bits.9)EQU(Assembled_Move_counter.ACC,11)MOV(Segment_12_Distance,Distance)MOV(Segment_12_Programmed_Speed,Programmed_Speed);
   14: XIO(Assembled_Move_counter.DN)XIC(Axis_Status_Bits.8)XIC(Axis_Status_Bits.9)EQU(Assembled_Move_counter.ACC,12)MOV(Segment_13_Distance,Distance)MOV(Segment_13_Programmed_Speed,Programmed_Speed);
   15: XIO(Assembled_Move_counter.DN)XIC(Axis_Status_Bits.8)XIC(Axis_Status_Bits.9)EQU(Assembled_Move_counter.ACC,13)MOV(Segment_14_Distance,Distance)MOV(Segment_14_Programmed_Speed,Programmed_Speed);
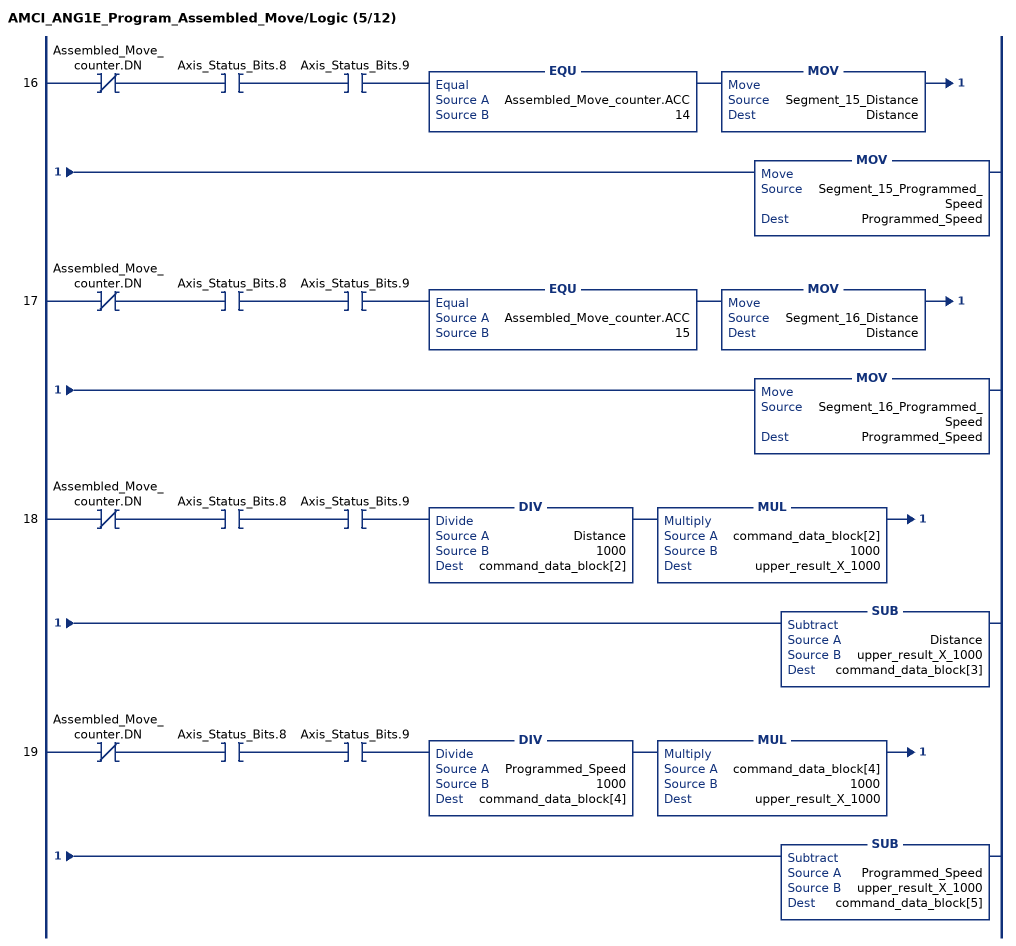
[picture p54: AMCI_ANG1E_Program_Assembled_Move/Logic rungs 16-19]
   16: XIO(Assembled_Move_counter.DN)XIC(Axis_Status_Bits.8)XIC(Axis_Status_Bits.9)EQU(Assembled_Move_counter.ACC,14)MOV(Segment_15_Distance,Distance)MOV(Segment_15_Programmed_Speed,Programmed_Speed);
   17: XIO(Assembled_Move_counter.DN)XIC(Axis_Status_Bits.8)XIC(Axis_Status_Bits.9)EQU(Assembled_Move_counter.ACC,15)MOV(Segment_16_Distance,Distance)MOV(Segment_16_Programmed_Speed,Programmed_Speed);
   18: XIO(Assembled_Move_counter.DN)XIC(Axis_Status_Bits.8)XIC(Axis_Status_Bits.9)DIV(Distance,1000,command_data_block[2])MUL(command_data_block[2],1000,upper_result_X_1000)SUB(Distance,upper_result_X_1000,command_data_block[3]);
   19: XIO(Assembled_Move_counter.DN)XIC(Axis_Status_Bits.8)XIC(Axis_Status_Bits.9)DIV(Programmed_Speed,1000,command_data_block[4])MUL(command_data_block[4],1000,upper_result_X_1000)SUB(Programmed_Speed,upper_result_X_1000,command_data_block[5]);
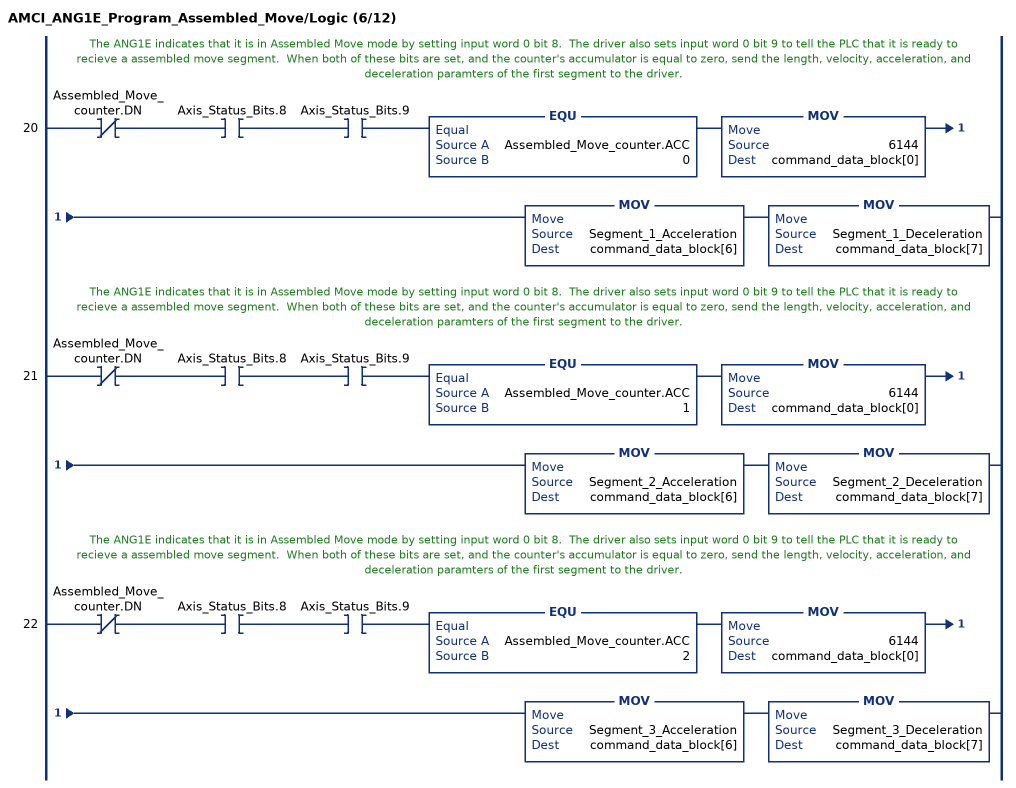
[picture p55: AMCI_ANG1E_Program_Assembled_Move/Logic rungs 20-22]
   // The ANG1E indicates that it is in Assembled Move mode by setting input word 0 bit 8.  The driver also sets input word 0 bit 9 to tell the PLC that it is ready to recieve a assembled move segment.  When both of these bits are set, and the counter's accumulator is equal to zero, send the length, velocity, acceleration, and deceleration paramters of the first segment to the driver.
   20: XIO(Assembled_Move_counter.DN)XIC(Axis_Status_Bits.8)XIC(Axis_Status_Bits.9)EQU(Assembled_Move_counter.ACC,0)MOV(6144,command_data_block[0])MOV(Segment_1_Acceleration,command_data_block[6])MOV(Segment_1_Deceleration,command_data_block[7]);
   // The ANG1E indicates that it is in Assembled Move mode by setting input word 0 bit 8.  The driver also sets input word 0 bit 9 to tell the PLC that it is ready to recieve a assembled move segment.  When both of these bits are set, and the counter's accumulator is equal to zero, send the length, velocity, acceleration, and deceleration paramters of the first segment to the driver.
   21: XIO(Assembled_Move_counter.DN)XIC(Axis_Status_Bits.8)XIC(Axis_Status_Bits.9)EQU(Assembled_Move_counter.ACC,1)MOV(6144,command_data_block[0])MOV(Segment_2_Acceleration,command_data_block[6])MOV(Segment_2_Deceleration,command_data_block[7]);
   // The ANG1E indicates that it is in Assembled Move mode by setting input word 0 bit 8.  The driver also sets input word 0 bit 9 to tell the PLC that it is ready to recieve a assembled move segment.  When both of these bits are set, and the counter's accumulator is equal to zero, send the length, velocity, acceleration, and deceleration paramters of the first segment to the driver.
   22: XIO(Assembled_Move_counter.DN)XIC(Axis_Status_Bits.8)XIC(Axis_Status_Bits.9)EQU(Assembled_Move_counter.ACC,2)MOV(6144,command_data_block[0])MOV(Segment_3_Acceleration,command_data_block[6])MOV(Segment_3_Deceleration,command_data_block[7]);
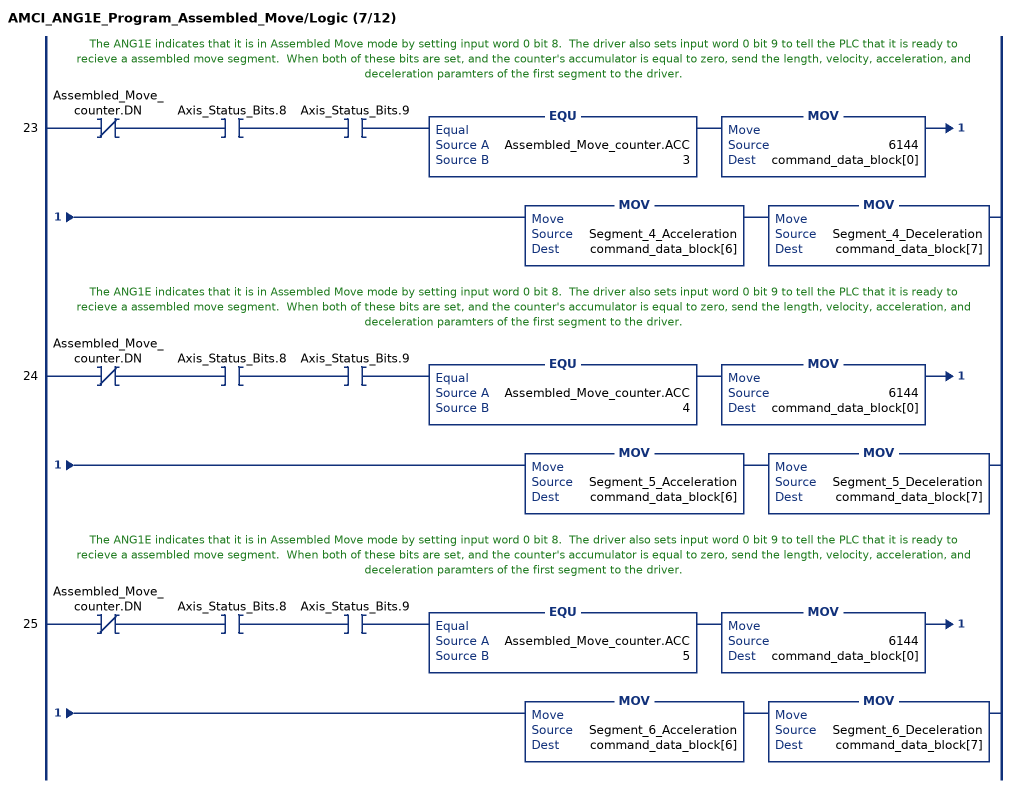
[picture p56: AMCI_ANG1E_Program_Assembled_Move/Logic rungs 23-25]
   // The ANG1E indicates that it is in Assembled Move mode by setting input word 0 bit 8.  The driver also sets input word 0 bit 9 to tell the PLC that it is ready to recieve a assembled move segment.  When both of these bits are set, and the counter's accumulator is equal to zero, send the length, velocity, acceleration, and deceleration paramters of the first segment to the driver.
   23: XIO(Assembled_Move_counter.DN)XIC(Axis_Status_Bits.8)XIC(Axis_Status_Bits.9)EQU(Assembled_Move_counter.ACC,3)MOV(6144,command_data_block[0])MOV(Segment_4_Acceleration,command_data_block[6])MOV(Segment_4_Deceleration,command_data_block[7]);
   // The ANG1E indicates that it is in Assembled Move mode by setting input word 0 bit 8.  The driver also sets input word 0 bit 9 to tell the PLC that it is ready to recieve a assembled move segment.  When both of these bits are set, and the counter's accumulator is equal to zero, send the length, velocity, acceleration, and deceleration paramters of the first segment to the driver.
   24: XIO(Assembled_Move_counter.DN)XIC(Axis_Status_Bits.8)XIC(Axis_Status_Bits.9)EQU(Assembled_Move_counter.ACC,4)MOV(6144,command_data_block[0])MOV(Segment_5_Acceleration,command_data_block[6])MOV(Segment_5_Deceleration,command_data_block[7]);
   // The ANG1E indicates that it is in Assembled Move mode by setting input word 0 bit 8.  The driver also sets input word 0 bit 9 to tell the PLC that it is ready to recieve a assembled move segment.  When both of these bits are set, and the counter's accumulator is equal to zero, send the length, velocity, acceleration, and deceleration paramters of the first segment to the driver.
   25: XIO(Assembled_Move_counter.DN)XIC(Axis_Status_Bits.8)XIC(Axis_Status_Bits.9)EQU(Assembled_Move_counter.ACC,5)MOV(6144,command_data_block[0])MOV(Segment_6_Acceleration,command_data_block[6])MOV(Segment_6_Deceleration,command_data_block[7]);
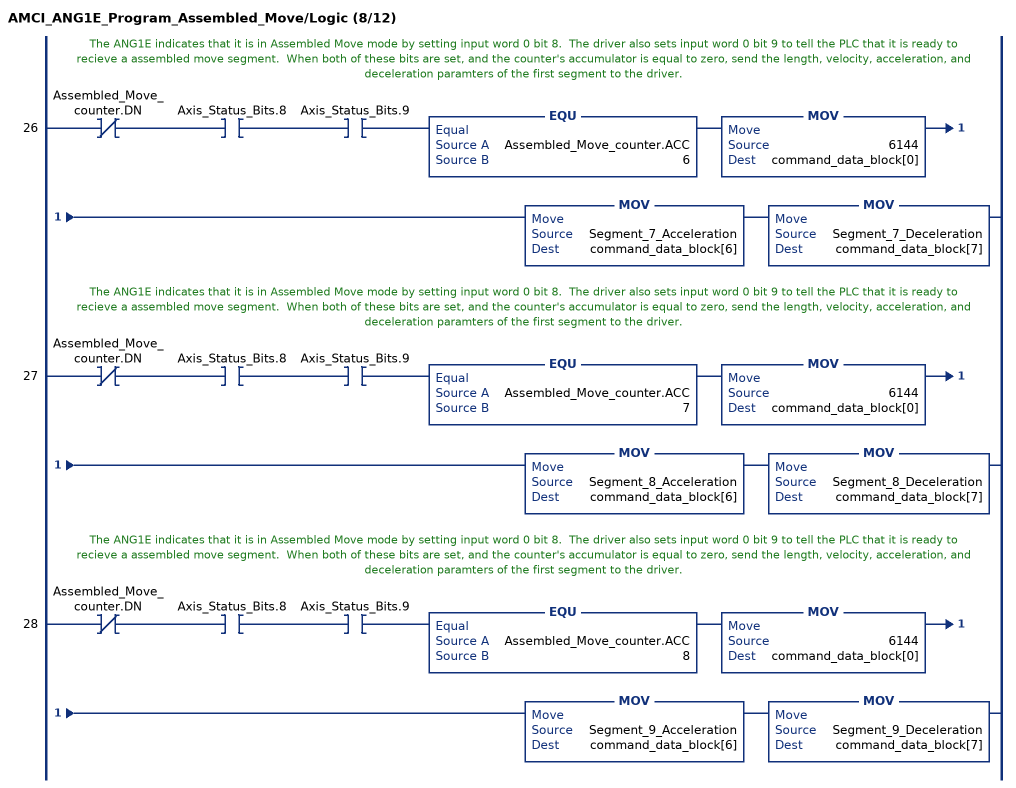
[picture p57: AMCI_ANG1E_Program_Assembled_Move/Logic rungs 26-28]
   // The ANG1E indicates that it is in Assembled Move mode by setting input word 0 bit 8.  The driver also sets input word 0 bit 9 to tell the PLC that it is ready to recieve a assembled move segment.  When both of these bits are set, and the counter's accumulator is equal to zero, send the length, velocity, acceleration, and deceleration paramters of the first segment to the driver.
   26: XIO(Assembled_Move_counter.DN)XIC(Axis_Status_Bits.8)XIC(Axis_Status_Bits.9)EQU(Assembled_Move_counter.ACC,6)MOV(6144,command_data_block[0])MOV(Segment_7_Acceleration,command_data_block[6])MOV(Segment_7_Deceleration,command_data_block[7]);
   // The ANG1E indicates that it is in Assembled Move mode by setting input word 0 bit 8.  The driver also sets input word 0 bit 9 to tell the PLC that it is ready to recieve a assembled move segment.  When both of these bits are set, and the counter's accumulator is equal to zero, send the length, velocity, acceleration, and deceleration paramters of the first segment to the driver.
   27: XIO(Assembled_Move_counter.DN)XIC(Axis_Status_Bits.8)XIC(Axis_Status_Bits.9)EQU(Assembled_Move_counter.ACC,7)MOV(6144,command_data_block[0])MOV(Segment_8_Acceleration,command_data_block[6])MOV(Segment_8_Deceleration,command_data_block[7]);
   // The ANG1E indicates that it is in Assembled Move mode by setting input word 0 bit 8.  The driver also sets input word 0 bit 9 to tell the PLC that it is ready to recieve a assembled move segment.  When both of these bits are set, and the counter's accumulator is equal to zero, send the length, velocity, acceleration, and deceleration paramters of the first segment to the driver.
   28: XIO(Assembled_Move_counter.DN)XIC(Axis_Status_Bits.8)XIC(Axis_Status_Bits.9)EQU(Assembled_Move_counter.ACC,8)MOV(6144,command_data_block[0])MOV(Segment_9_Acceleration,command_data_block[6])MOV(Segment_9_Deceleration,command_data_block[7]);
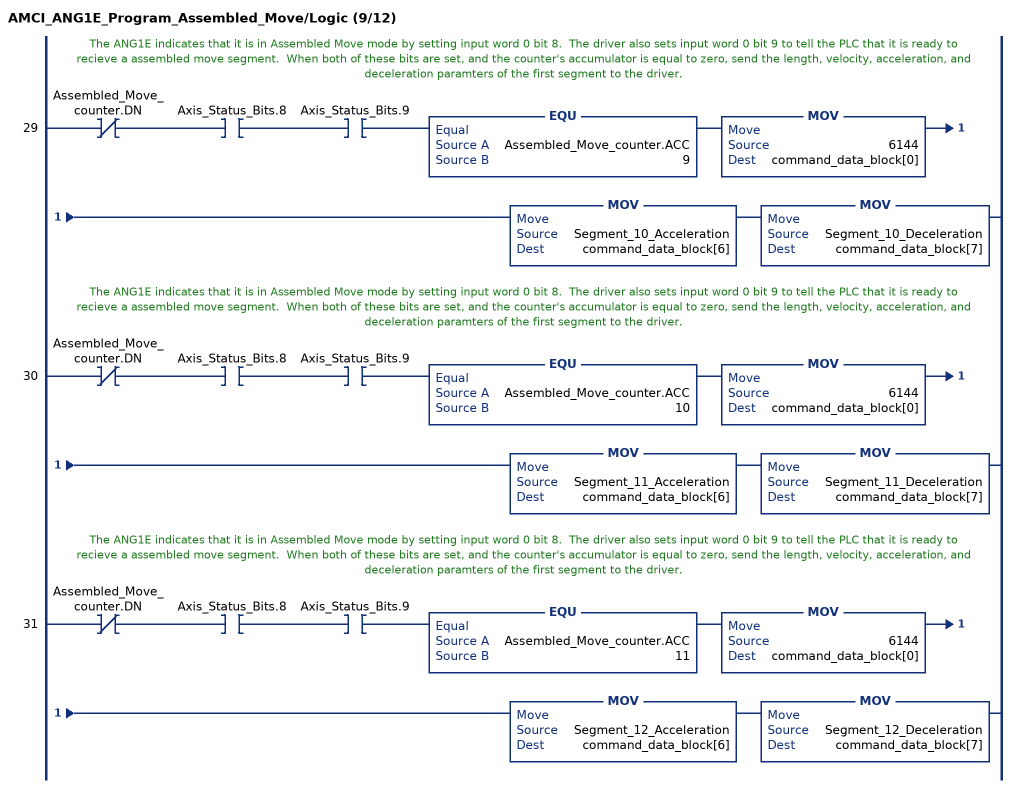
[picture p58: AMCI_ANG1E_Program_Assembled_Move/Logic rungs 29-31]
   // The ANG1E indicates that it is in Assembled Move mode by setting input word 0 bit 8.  The driver also sets input word 0 bit 9 to tell the PLC that it is ready to recieve a assembled move segment.  When both of these bits are set, and the counter's accumulator is equal to zero, send the length, velocity, acceleration, and deceleration paramters of the first segment to the driver.
   29: XIO(Assembled_Move_counter.DN)XIC(Axis_Status_Bits.8)XIC(Axis_Status_Bits.9)EQU(Assembled_Move_counter.ACC,9)MOV(6144,command_data_block[0])MOV(Segment_10_Acceleration,command_data_block[6])MOV(Segment_10_Deceleration,command_data_block[7]);
   // The ANG1E indicates that it is in Assembled Move mode by setting input word 0 bit 8.  The driver also sets input word 0 bit 9 to tell the PLC that it is ready to recieve a assembled move segment.  When both of these bits are set, and the counter's accumulator is equal to zero, send the length, velocity, acceleration, and deceleration paramters of the first segment to the driver.
   30: XIO(Assembled_Move_counter.DN)XIC(Axis_Status_Bits.8)XIC(Axis_Status_Bits.9)EQU(Assembled_Move_counter.ACC,10)MOV(6144,command_data_block[0])MOV(Segment_11_Acceleration,command_data_block[6])MOV(Segment_11_Deceleration,command_data_block[7]);
   // The ANG1E indicates that it is in Assembled Move mode by setting input word 0 bit 8.  The driver also sets input word 0 bit 9 to tell the PLC that it is ready to recieve a assembled move segment.  When both of these bits are set, and the counter's accumulator is equal to zero, send the length, velocity, acceleration, and deceleration paramters of the first segment to the driver.
   31: XIO(Assembled_Move_counter.DN)XIC(Axis_Status_Bits.8)XIC(Axis_Status_Bits.9)EQU(Assembled_Move_counter.ACC,11)MOV(6144,command_data_block[0])MOV(Segment_12_Acceleration,command_data_block[6])MOV(Segment_12_Deceleration,command_data_block[7]);
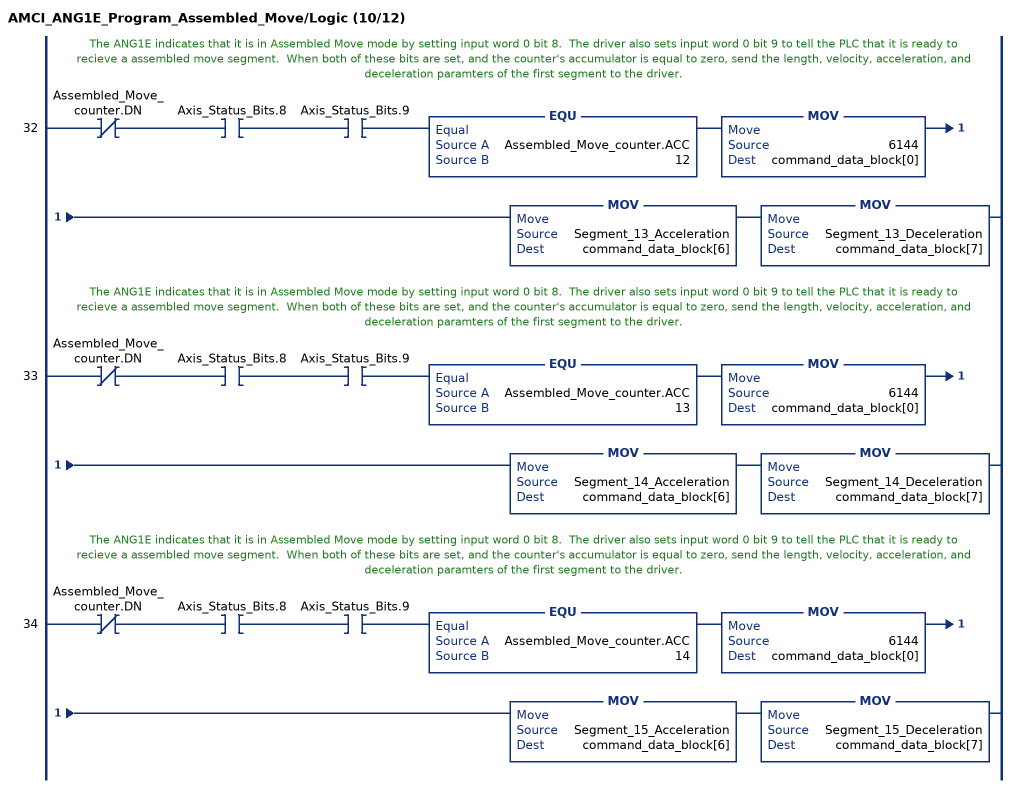
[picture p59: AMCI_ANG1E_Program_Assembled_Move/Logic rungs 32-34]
   // The ANG1E indicates that it is in Assembled Move mode by setting input word 0 bit 8.  The driver also sets input word 0 bit 9 to tell the PLC that it is ready to recieve a assembled move segment.  When both of these bits are set, and the counter's accumulator is equal to zero, send the length, velocity, acceleration, and deceleration paramters of the first segment to the driver.
   32: XIO(Assembled_Move_counter.DN)XIC(Axis_Status_Bits.8)XIC(Axis_Status_Bits.9)EQU(Assembled_Move_counter.ACC,12)MOV(6144,command_data_block[0])MOV(Segment_13_Acceleration,command_data_block[6])MOV(Segment_13_Deceleration,command_data_block[7]);
   // The ANG1E indicates that it is in Assembled Move mode by setting input word 0 bit 8.  The driver also sets input word 0 bit 9 to tell the PLC that it is ready to recieve a assembled move segment.  When both of these bits are set, and the counter's accumulator is equal to zero, send the length, velocity, acceleration, and deceleration paramters of the first segment to the driver.
   33: XIO(Assembled_Move_counter.DN)XIC(Axis_Status_Bits.8)XIC(Axis_Status_Bits.9)EQU(Assembled_Move_counter.ACC,13)MOV(6144,command_data_block[0])MOV(Segment_14_Acceleration,command_data_block[6])MOV(Segment_14_Deceleration,command_data_block[7]);
   // The ANG1E indicates that it is in Assembled Move mode by setting input word 0 bit 8.  The driver also sets input word 0 bit 9 to tell the PLC that it is ready to recieve a assembled move segment.  When both of these bits are set, and the counter's accumulator is equal to zero, send the length, velocity, acceleration, and deceleration paramters of the first segment to the driver.
   34: XIO(Assembled_Move_counter.DN)XIC(Axis_Status_Bits.8)XIC(Axis_Status_Bits.9)EQU(Assembled_Move_counter.ACC,14)MOV(6144,command_data_block[0])MOV(Segment_15_Acceleration,command_data_block[6])MOV(Segment_15_Deceleration,command_data_block[7]);
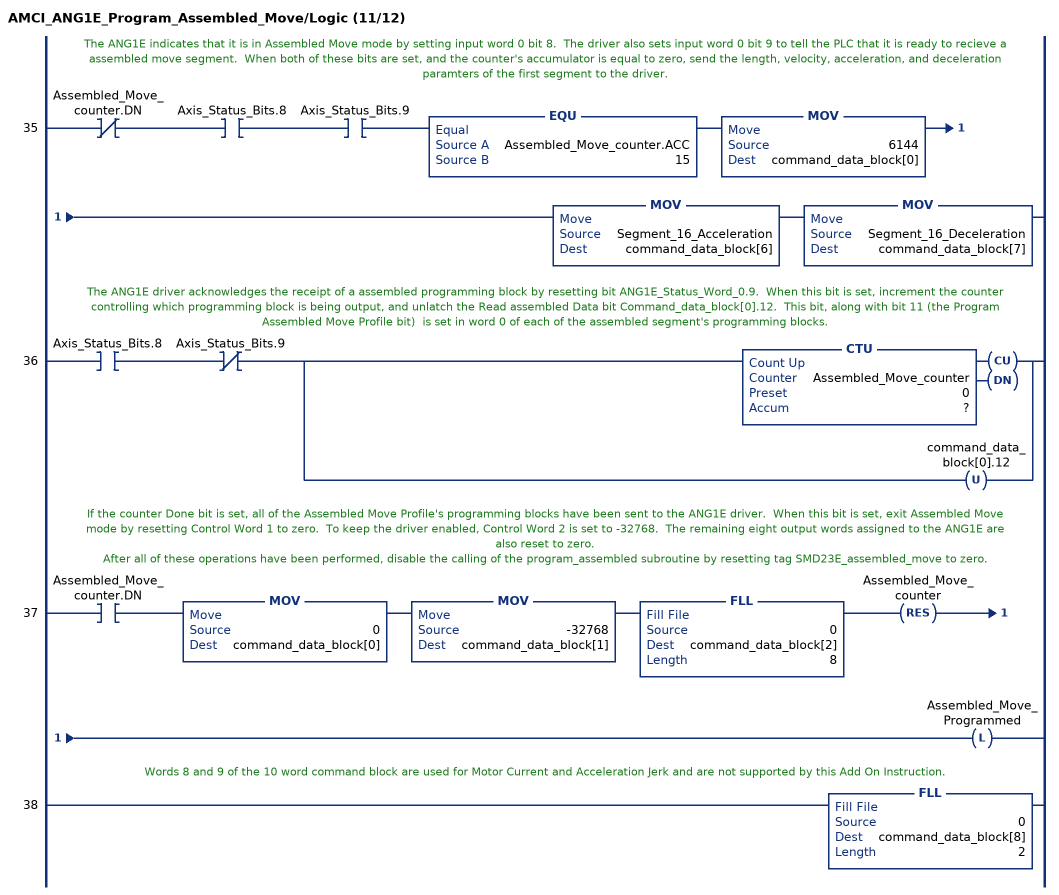
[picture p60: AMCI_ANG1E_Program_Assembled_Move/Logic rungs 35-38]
   // The ANG1E indicates that it is in Assembled Move mode by setting input word 0 bit 8.  The driver also sets input word 0 bit 9 to tell the PLC that it is ready to recieve a assembled move segment.  When both of these bits are set, and the counter's accumulator is equal to zero, send the length, velocity, acceleration, and deceleration paramters of the first segment to the driver.
   35: XIO(Assembled_Move_counter.DN)XIC(Axis_Status_Bits.8)XIC(Axis_Status_Bits.9)EQU(Assembled_Move_counter.ACC,15)MOV(6144,command_data_block[0])MOV(Segment_16_Acceleration,command_data_block[6])MOV(Segment_16_Deceleration,command_data_block[7]);
   // The ANG1E driver acknowledges the receipt of a assembled programming block by resetting bit ANG1E_Status_Word_0.9.  When this bit is set, increment the counter controlling which programming block is being output, and unlatch the Read assembled Data bit Command_data_block[0].12.  This bit, along with bit 11 (the Program Assembled Move Profile bit)  is set in word 0 of each of the assembled segment's programming blocks.
   36: XIC(Axis_Status_Bits.8)XIO(Axis_Status_Bits.9)[CTU(Assembled_Move_counter,?,?) ,OTU(command_data_block[0].12) ];
   // If the counter Done bit is set, all of the Assembled Move Profile's programming blocks have been sent to the ANG1E driver.  When this bit is set, exit Assembled Move mode by resetting Control Word 1 to zero.  To keep the driver enabled, Control Word 2 is set to -32768.  The remaining eight output words assigned to the ANG1E are also reset to zero.
   // After all of these operations have been performed, disable the calling of the program_assembled subroutine by resetting tag SMD23E_assembled_move to zero.
   37: XIC(Assembled_Move_counter.DN)MOV(0,command_data_block[0])MOV(-32768,command_data_block[1])FLL(0,command_data_block[2],8)RES(Assembled_Move_counter)OTL(Assembled_Move_Programmed);
   // Words 8 and 9 of the 10 word command block are used for Motor Current and Acceleration Jerk and are not supported by this Add On Instruction.
   38: FLL(0,command_data_block[8],2);
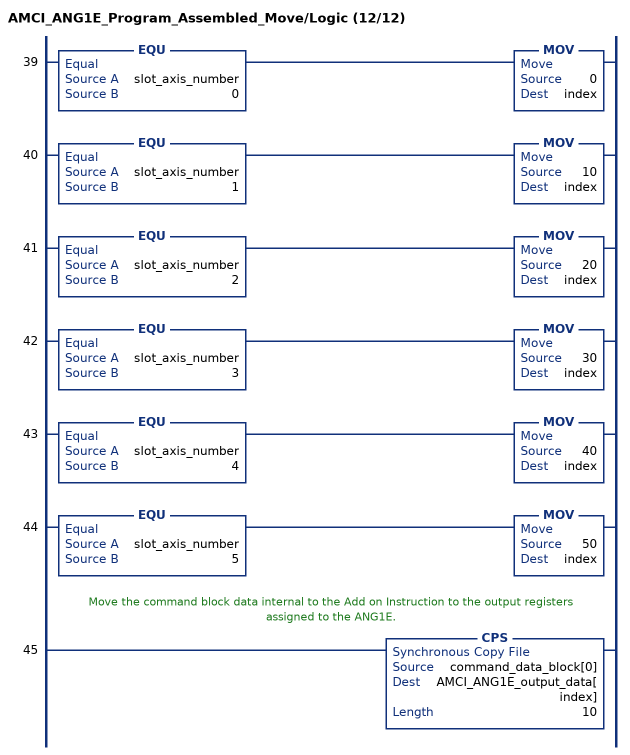
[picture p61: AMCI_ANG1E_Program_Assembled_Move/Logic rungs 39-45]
   39: EQU(slot_axis_number,0)MOV(0,index);
   40: EQU(slot_axis_number,1)MOV(10,index);
   41: EQU(slot_axis_number,2)MOV(20,index);
   42: EQU(slot_axis_number,3)MOV(30,index);
   43: EQU(slot_axis_number,4)MOV(40,index);
   44: EQU(slot_axis_number,5)MOV(50,index);
   // Move the command block data internal to the Add on Instruction to the output registers assigned to the ANG1E.
   45: CPS(command_data_block[0],AMCI_ANG1E_output_data[index],10);
END_ROUTINE
END_ADD_ON_INSTRUCTION
